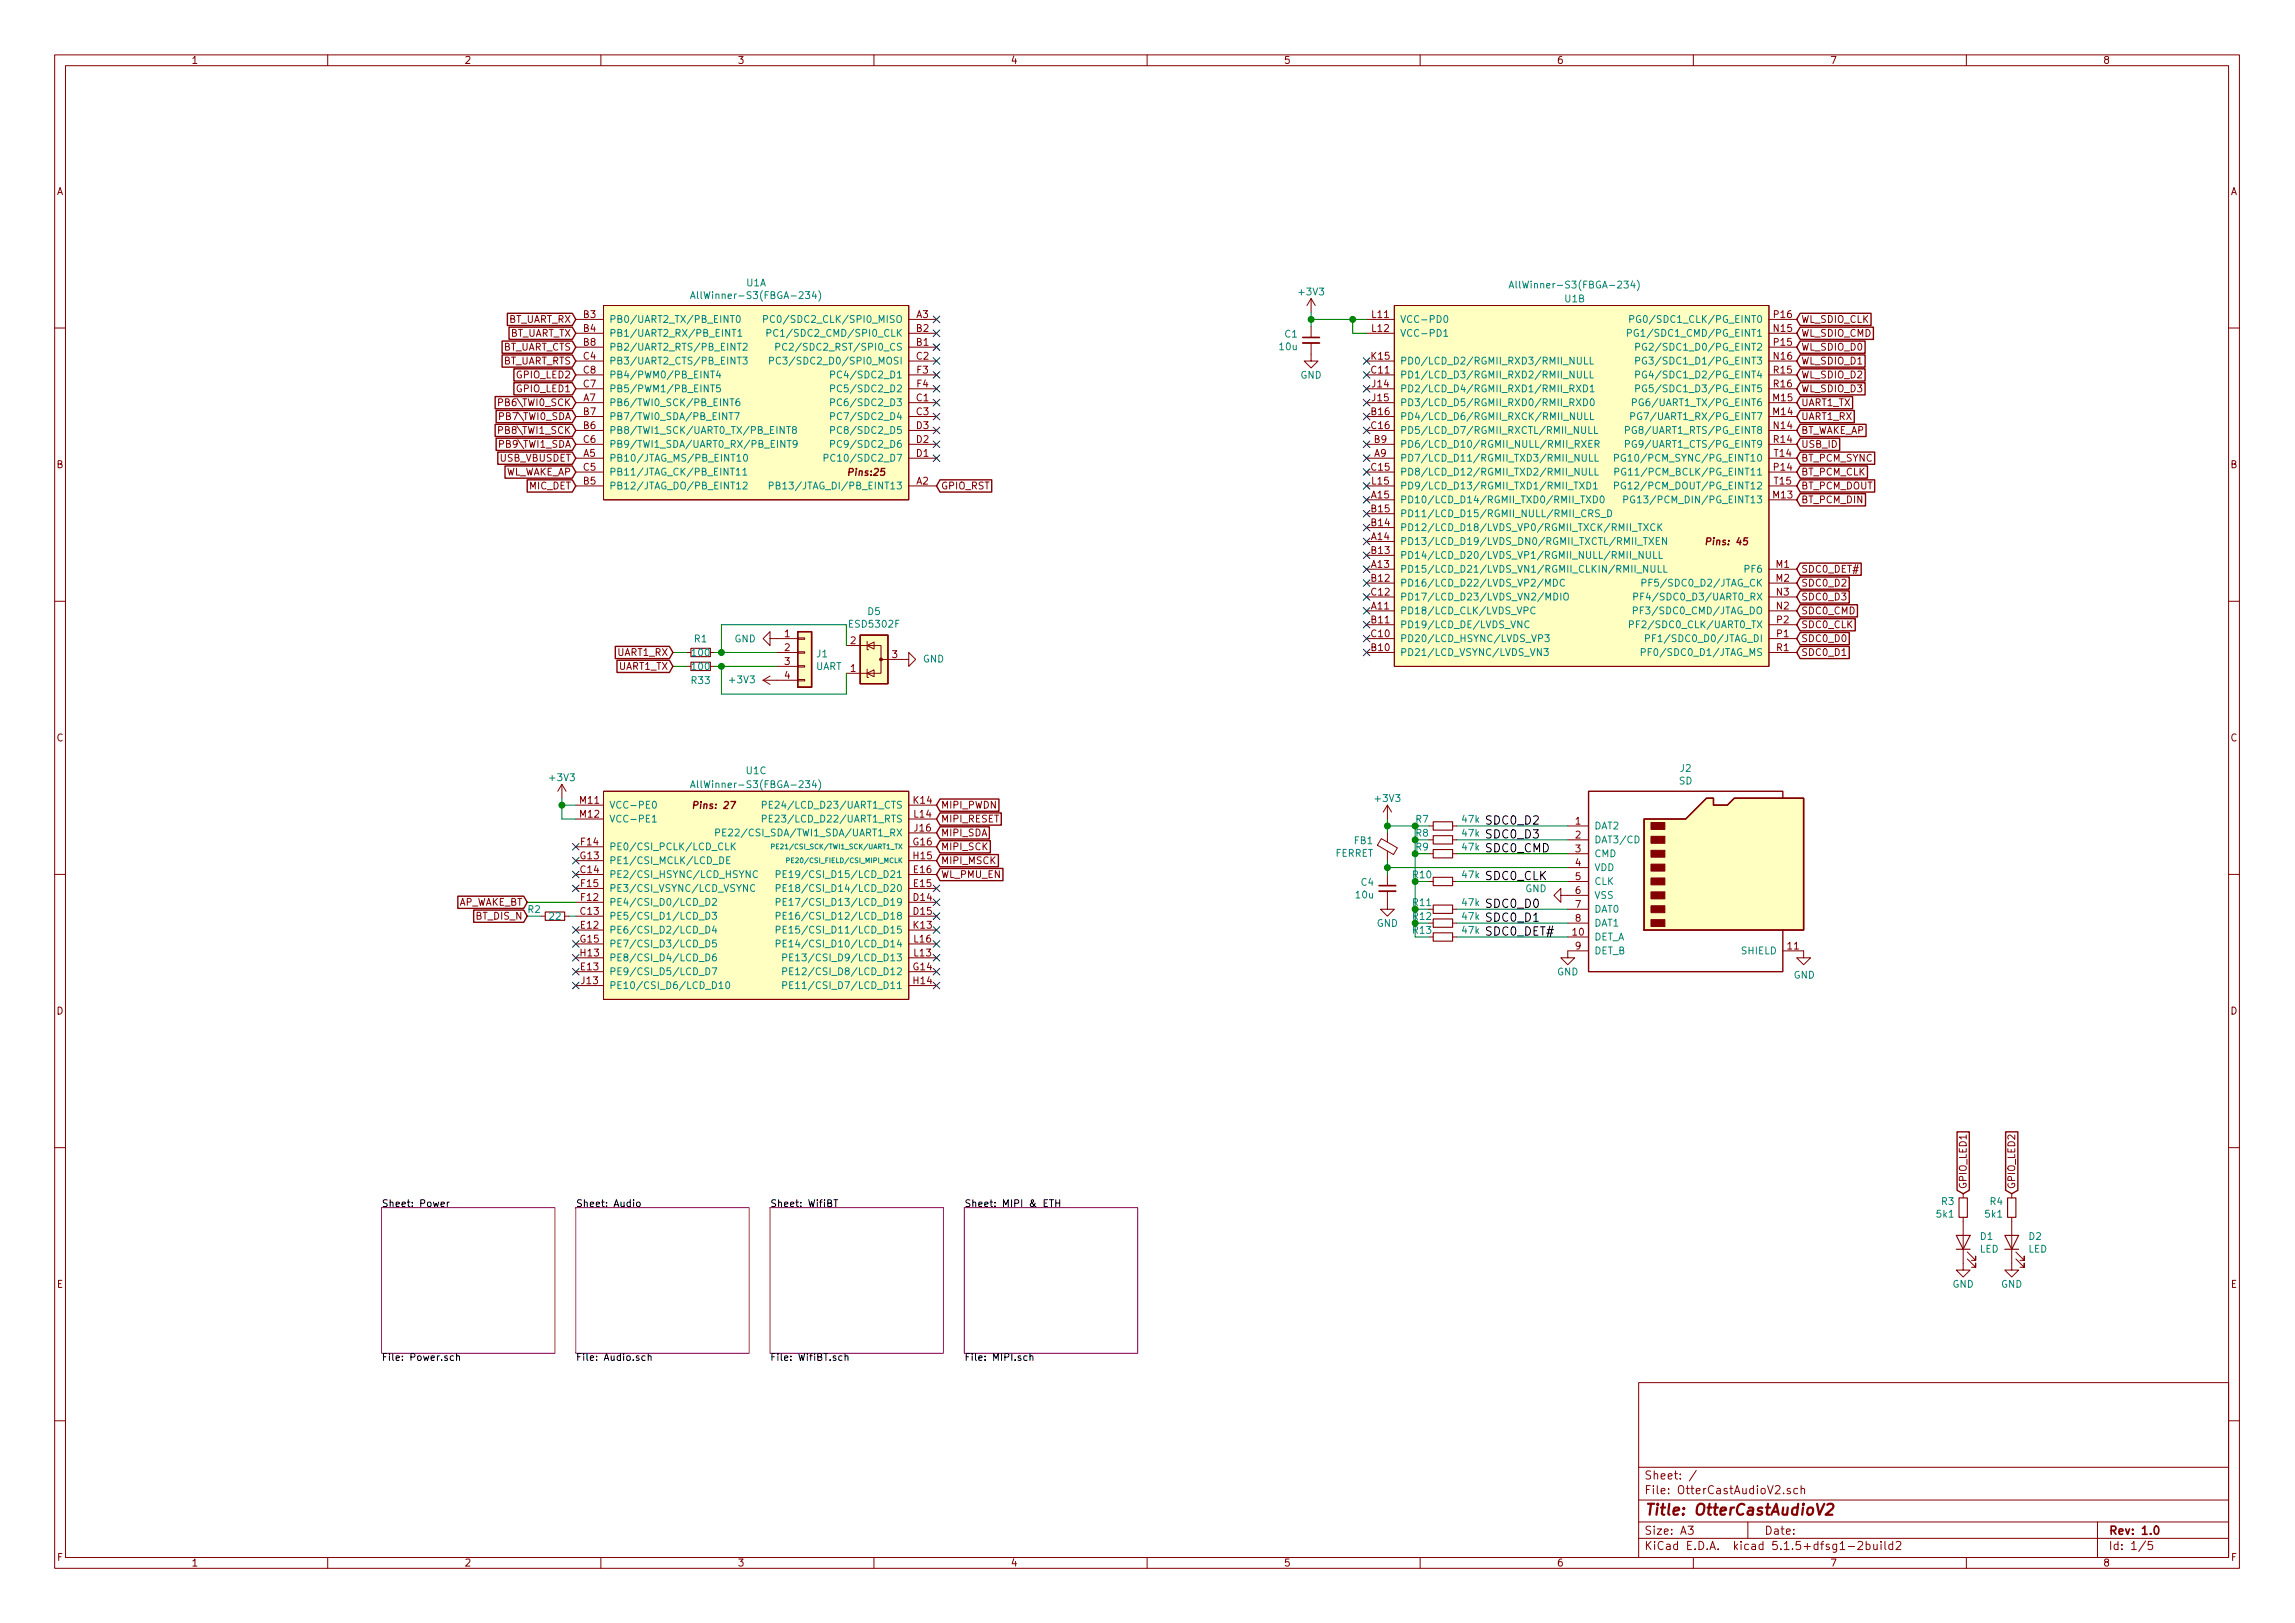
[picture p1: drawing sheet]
<svg xmlns="http://www.w3.org/2000/svg" width="420mm" height="297mm" viewBox="0 0 420 297" stroke-linecap="round" stroke-linejoin="round" font-family="sans-serif">
<defs><g id="words">
<text font-size="2.8" fill="#840000" x="301" y="277.3">Title: OtterCastAudioV2</text>
<g font-size="2.1">
<text x="271.8" y="153.5">SDC0_D3</text>
<text x="271.8" y="150.9">SDC0_D2</text>
<text x="271.8" y="156">SDC0_CMD</text>
<text x="271.8" y="161.1">SDC0_CLK</text>
<text x="271.8" y="166.2">SDC0_D0</text>
<text x="271.8" y="171.2">SDC0_DET#</text>
<text x="271.8" y="168.7">SDC0_D1</text>
</g>
<g font-size="2.1" fill="#840000">
<text x="301" y="273.5">File: OtterCastAudioV2.sch</text>
<text x="301" y="270.8">Sheet: /</text>
<text x="301" y="280.9">Size: A3</text>
<text x="323" y="280.9">Date:</text>
<text x="386" y="280.9">Rev: 1.0</text>
<text x="301" y="283.7">KiCad E.D.A. kicad 5.1.5+dfsg1-2build2</text>
<text x="386" y="283.7">Id: 1/5</text>
</g>
<g font-size="1.8" fill="#840000">
<text x="35" y="11.7">1</text>
<text x="85" y="11.7">2</text>
<text x="135" y="11.7">3</text>
<text x="185" y="11.7">4</text>
<text x="235" y="11.7">5</text>
<text x="285" y="11.7">6</text>
<text x="335" y="11.7">7</text>
<text x="385" y="11.7">8</text>
<text x="10.4" y="35.7">A</text>
<text x="408.4" y="35.7">A</text>
<text x="92.9" y="59.1">BT_UART_RX</text>
<text x="106.8" y="58.2">B3</text>
<text x="167.8" y="58.2">A3</text>
<text x="251.2" y="58.2">L11</text>
<text x="324.8" y="58.2">P16</text>
<text x="329.7" y="59.1">WL_SDIO_CLK</text>
<text x="91.8" y="64.2">BT_UART_CTS</text>
<text x="93.1" y="61.6">BT_UART_TX</text>
<text x="106.8" y="60.7">B4</text>
<text x="106.8" y="63.3">B8</text>
<text x="106.8" y="65.8">C4</text>
<text x="167.8" y="63.3">B1</text>
<text x="167.8" y="60.7">B2</text>
<text x="167.8" y="65.8">C2</text>
<text x="251.1" y="65.8">K15</text>
<text x="251.2" y="60.7">L12</text>
<text x="324.8" y="60.7">N15</text>
<text x="324.8" y="65.8">N16</text>
<text x="324.8" y="63.3">P15</text>
<text x="329.7" y="61.6">WL_SDIO_CMD</text>
<text x="329.7" y="64.2">WL_SDIO_D0</text>
<text x="91.8" y="66.7">BT_UART_RTS</text>
<text x="94.7" y="71.8">GPIO_LED1</text>
<text x="94.7" y="69.3">GPIO_LED2</text>
<text x="106.8" y="70.9">C7</text>
<text x="106.8" y="68.4">C8</text>
<text x="167.9" y="68.4">F3</text>
<text x="167.9" y="70.9">F4</text>
<text x="251.1" y="68.4">C11</text>
<text x="251.3" y="70.9">J14</text>
<text x="324.8" y="68.4">R15</text>
<text x="324.8" y="70.9">R16</text>
<text x="329.7" y="69.3">WL_SDIO_D2</text>
<text x="329.7" y="66.7">WL_SDIO_D1</text>
<text x="329.7" y="71.8">WL_SDIO_D3</text>
<text x="91.7" y="74.3">PB6\TWI0_SCK</text>
<text x="91.7" y="76.9">PB7\TWI0_SDA</text>
<text x="106.8" y="73.4">A7</text>
<text x="106.8" y="76">B7</text>
<text x="167.8" y="73.4">C1</text>
<text x="167.8" y="76">C3</text>
<text x="251.1" y="76">B16</text>
<text x="251.3" y="73.4">J15</text>
<text x="324.7" y="76">M14</text>
<text x="324.7" y="73.4">M15</text>
<text x="329.7" y="74.3">UART1_TX</text>
<text x="329.7" y="76.9">UART1_RX</text>
<text x="91.7" y="79.4">PB8\TWI1_SCK</text>
<text x="91.7" y="82">PB9\TWI1_SDA</text>
<text x="106.8" y="83.6">A5</text>
<text x="106.8" y="78.5">B6</text>
<text x="106.8" y="81.1">C6</text>
<text x="167.8" y="83.6">D1</text>
<text x="167.8" y="81.1">D2</text>
<text x="167.8" y="78.5">D3</text>
<text x="251.1" y="78.5">C16</text>
<text x="251.6" y="83.6">A9</text>
<text x="251.6" y="81.1">B9</text>
<text x="324.8" y="78.5">N14</text>
<text x="324.8" y="81.1">R14</text>
<text x="324.9" y="83.6">T14</text>
<text x="329.7" y="82">USB_ID</text>
<text x="329.7" y="79.4">BT_WAKE_AP</text>
<text x="10.4" y="85.7">B</text>
<text x="91.5" y="84.5">USB_VBUSDET</text>
<text x="92" y="87">WL_WAKE_AP</text>
<text x="96.9" y="89.6">MIC_DET</text>
<text x="106.8" y="88.7">B5</text>
<text x="106.8" y="86.1">C5</text>
<text x="155.6" y="87.1">Pins:25</text>
<text x="167.8" y="88.7">A2</text>
<text x="172.2" y="89.6">GPIO_RST</text>
<text x="251.1" y="86.1">C15</text>
<text x="251.2" y="88.7">L15</text>
<text x="324.8" y="86.1">P14</text>
<text x="324.9" y="88.7">T15</text>
<text x="329.7" y="84.5">BT_PCM_SYNC</text>
<text x="329.7" y="87">BT_PCM_CLK</text>
<text x="329.7" y="89.6">BT_PCM_DOUT</text>
<text x="408.4" y="85.7">B</text>
<text x="251.1" y="91.2">A15</text>
<text x="251.1" y="93.8">B15</text>
<text x="324.7" y="91.2">M13</text>
<text x="329.7" y="92.1">BT_PCM_DIN</text>
<text x="251.1" y="98.8">A14</text>
<text x="251.1" y="101.4">B13</text>
<text x="251.1" y="96.3">B14</text>
<text x="312.9" y="99.8">Pins: 45</text>
<text x="251.1" y="103.9">A13</text>
<text x="251.1" y="106.5">B12</text>
<text x="325.2" y="103.9">M1</text>
<text x="325.2" y="106.5">M2</text>
<text x="329.7" y="104.8">SDC0_DET#</text>
<text x="329.7" y="107.4">SDC0_D2</text>
<text x="251.1" y="111.5">A11</text>
<text x="251.1" y="109">C12</text>
<text x="325.3" y="111.5">N2</text>
<text x="325.3" y="109">N3</text>
<text x="329.7" y="109.9">SDC0_D3</text>
<text x="329.7" y="112.4">SDC0_CMD</text>
<text x="143.7" y="116.6">1</text>
<text x="143.7" y="119.2">2</text>
<text x="155.7" y="117.9">2</text>
<text x="251.1" y="119.2">B10</text>
<text x="251.1" y="114.1">B11</text>
<text x="251.1" y="116.6">C10</text>
<text x="325.3" y="119.2">R1</text>
<text x="325.3" y="116.6">P1</text>
<text x="325.3" y="114.1">P2</text>
<text x="329.7" y="117.5">SDC0_D0</text>
<text x="329.7" y="115">SDC0_CLK</text>
<text x="113.1" y="120.1">UART1_RX</text>
<text x="113.3" y="122.6">UART1_TX</text>
<text x="143.7" y="121.7">3</text>
<text x="143.7" y="124.2">4</text>
<text x="155.7" y="123">1</text>
<text x="163.3" y="120.4">3</text>
<text x="329.7" y="120.1">SDC0_D1</text>
<text x="10.4" y="135.7">C</text>
<text x="408.4" y="135.7">C</text>
<text x="106.2" y="147.1">M11</text>
<text x="106.2" y="149.6">M12</text>
<text x="127.4" y="148">Pins: 27</text>
<text x="167.3" y="147.1">K14</text>
<text x="167.4" y="149.6">L14</text>
<text x="172.2" y="148">MIPI_PWDN</text>
<text x="106.4" y="154.7">F14</text>
<text x="167.2" y="154.7">G16</text>
<text x="167.4" y="152.2">J16</text>
<text x="172.2" y="153.1">MIPI_SDA</text>
<text x="172.2" y="155.6">MIPI_SCK</text>
<text x="172.2" y="150.5">MIPI_RESET</text>
<text x="288.4" y="150.9">1</text>
<text x="288.4" y="153.5">2</text>
<text x="288.4" y="156">3</text>
<text x="106.3" y="157.3">G13</text>
<text x="106.3" y="159.8">C14</text>
<text x="167.3" y="157.3">H15</text>
<text x="167.3" y="159.8">E16</text>
<text x="172.2" y="158.2">MIPI_MSCK</text>
<text x="172.2" y="160.7">WL_PMU_EN</text>
<text x="288.4" y="158.5">4</text>
<text x="288.4" y="161.1">5</text>
<text x="83.5" y="165.8">AP_WAKE_BT</text>
<text x="106.3" y="167.4">C13</text>
<text x="106.4" y="164.9">F12</text>
<text x="106.4" y="162.3">F15</text>
<text x="167.3" y="164.9">D14</text>
<text x="167.3" y="167.4">D15</text>
<text x="167.3" y="162.3">E15</text>
<text x="288.4" y="163.6">6</text>
<text x="288.4" y="166.2">7</text>
<text x="87.2" y="168.3">BT_DIS_N</text>
<text x="106.3" y="172.5">G15</text>
<text x="106.4" y="170">E12</text>
<text x="167.3" y="170">K13</text>
<text x="167.4" y="172.5">L16</text>
<text x="288" y="171.2">10</text>
<text x="288.4" y="168.7">8</text>
<text x="288.4" y="173.8">9</text>
<text x="327.3" y="173.8">11</text>
<text x="106.3" y="175">H13</text>
<text x="106.4" y="177.6">E13</text>
<text x="167.2" y="177.6">G14</text>
<text x="167.4" y="175">L13</text>
<text x="10.4" y="185.7">D</text>
<text x="106.5" y="180.1">J13</text>
<text x="167.3" y="180.1">H14</text>
<text x="408.4" y="185.7">D</text>
<text x="360" y="217.7" transform="rotate(-90 360 217.7)">GPIO_LED1</text>
<text x="368.9" y="217.7" transform="rotate(-90 368.9 217.7)">GPIO_LED2</text>
<text x="10.4" y="235.7">E</text>
<text x="408.4" y="235.7">E</text>
<text x="10.5" y="285.7">F</text>
<text x="35" y="286.7">1</text>
<text x="85" y="286.7">2</text>
<text x="135" y="286.7">3</text>
<text x="185" y="286.7">4</text>
<text x="235" y="286.7">5</text>
<text x="285" y="286.7">6</text>
<text x="335" y="286.7">7</text>
<text x="385" y="286.7">8</text>
<text x="408.5" y="285.7">F</text>
</g>
<g font-size="1.8" fill="#008484">
<text x="136.7" y="52.4">U1A</text>
<text x="277.9" y="52.8">AllWinner-S3(FBGA-234)</text>
<text x="111.5" y="59.1">PB0/UART2_TX/PB_EINT0</text>
<text x="128.1" y="54.7">AllWinner-S3(FBGA-234)</text>
<text x="142.3" y="59.1">PC0/SDC2_CLK/SPI0_MISO</text>
<text x="237.9" y="54.1">+3V3</text>
<text x="256.3" y="59.1">VCC-PD0</text>
<text x="286.5" y="55.3">U1B</text>
<text x="300.4" y="59.1">PG0/SDC1_CLK/PG_EINT0</text>
<text x="111.5" y="61.6">PB1/UART2_RX/PB_EINT1</text>
<text x="111.5" y="64.2">PB2/UART2_RTS/PB_EINT2</text>
<text x="142.7" y="61.6">PC1/SDC2_CMD/SPI0_CLK</text>
<text x="144.4" y="64.2">PC2/SDC2_RST/SPI0_CS</text>
<text x="234.3" y="64.1">10u</text>
<text x="235.3" y="61.8">C1</text>
<text x="256.3" y="61.6">VCC-PD1</text>
<text x="300" y="61.6">PG1/SDC1_CMD/PG_EINT1</text>
<text x="301.8" y="64.2">PG2/SDC1_D0/PG_EINT2</text>
<text x="111.5" y="66.7">PB3/UART2_CTS/PB_EINT3</text>
<text x="111.5" y="71.8">PB5/PWM1/PB_EINT5</text>
<text x="111.5" y="69.3">PB4/PWM0/PB_EINT4</text>
<text x="143.6" y="66.7">PC3/SDC2_D0/SPI0_MOSI</text>
<text x="153.5" y="69.3">PC4/SDC2_D1</text>
<text x="153.5" y="71.8">PC5/SDC2_D2</text>
<text x="238.1" y="69.3">GND</text>
<text x="256.3" y="69.3">PD1/LCD_D3/RGMII_RXD2/RMII_NULL</text>
<text x="256.3" y="71.8">PD2/LCD_D4/RGMII_RXD1/RMII_RXD1</text>
<text x="256.3" y="66.7">PD0/LCD_D2/RGMII_RXD3/RMII_NULL</text>
<text x="301.8" y="66.7">PG3/SDC1_D1/PG_EINT3</text>
<text x="301.8" y="69.3">PG4/SDC1_D2/PG_EINT4</text>
<text x="301.8" y="71.8">PG5/SDC1_D3/PG_EINT5</text>
<text x="111.5" y="74.3">PB6/TWI0_SCK/PB_EINT6</text>
<text x="111.5" y="76.9">PB7/TWI0_SDA/PB_EINT7</text>
<text x="153.5" y="74.3">PC6/SDC2_D3</text>
<text x="153.5" y="76.9">PC7/SDC2_D4</text>
<text x="256.3" y="76.9">PD4/LCD_D6/RGMII_RXCK/RMII_NULL</text>
<text x="256.3" y="74.3">PD3/LCD_D5/RGMII_RXD0/RMII_RXD0</text>
<text x="300.4" y="76.9">PG7/UART1_RX/PG_EINT7</text>
<text x="300.6" y="74.3">PG6/UART1_TX/PG_EINT6</text>
<text x="111.5" y="79.4">PB8/TWI1_SCK/UART0_TX/PB_EINT8</text>
<text x="111.5" y="82">PB9/TWI1_SDA/UART0_RX/PB_EINT9</text>
<text x="153.5" y="82">PC9/SDC2_D6</text>
<text x="153.5" y="79.4">PC8/SDC2_D5</text>
<text x="256.3" y="82">PD6/LCD_D10/RGMII_NULL/RMII_RXER</text>
<text x="256.3" y="79.4">PD5/LCD_D7/RGMII_RXCTL/RMII_NULL</text>
<text x="299.3" y="79.4">PG8/UART1_RTS/PG_EINT8</text>
<text x="299.3" y="82">PG9/UART1_CTS/PG_EINT9</text>
<text x="111.5" y="84.5">PB10/JTAG_MS/PB_EINT10</text>
<text x="111.5" y="89.6">PB12/JTAG_DO/PB_EINT12</text>
<text x="111.5" y="87">PB11/JTAG_CK/PB_EINT11</text>
<text x="143.1" y="89.6">PB13/JTAG_DI/PB_EINT13</text>
<text x="152.5" y="84.5">PC10/SDC2_D7</text>
<text x="256.3" y="84.5">PD7/LCD_D11/RGMII_TXD3/RMII_NULL</text>
<text x="256.3" y="87">PD8/LCD_D12/RGMII_TXD2/RMII_NULL</text>
<text x="256.3" y="89.6">PD9/LCD_D13/RGMII_TXD1/RMII_TXD1</text>
<text x="297.9" y="89.6">PG12/PCM_DOUT/PG_EINT12</text>
<text x="298" y="87">PG11/PCM_BCLK/PG_EINT11</text>
<text x="298" y="84.5">PG10/PCM_SYNC/PG_EINT10</text>
<text x="256.3" y="92.1">PD10/LCD_D14/RGMII_TXD0/RMII_TXD0</text>
<text x="256.3" y="94.7">PD11/LCD_D15/RGMII_NULL/RMII_CRS_D</text>
<text x="299.8" y="92.1">PG13/PCM_DIN/PG_EINT13</text>
<text x="256.3" y="99.7">PD13/LCD_D19/LVDS_DN0/RGMII_TXCTL/RMII_TXEN</text>
<text x="256.3" y="97.2">PD12/LCD_D18/LVDS_VP0/RGMII_TXCK/RMII_TXCK</text>
<text x="256.3" y="104.8">PD15/LCD_D21/LVDS_VN1/RGMII_CLKIN/RMII_NULL</text>
<text x="256.3" y="107.4">PD16/LCD_D22/LVDS_VP2/MDC</text>
<text x="256.3" y="102.3">PD14/LCD_D20/LVDS_VP1/RGMII_NULL/RMII_NULL</text>
<text x="302.4" y="107.4">PF5/SDC0_D2/JTAG_CK</text>
<text x="319.6" y="104.8">PF6</text>
<text x="158.9" y="112.6">D5</text>
<text x="256.3" y="112.4">PD18/LCD_CLK/LVDS_VPC</text>
<text x="256.3" y="109.9">PD17/LCD_D23/LVDS_VN2/MDIO</text>
<text x="300.5" y="112.4">PF3/SDC0_CMD/JTAG_DO</text>
<text x="301.3" y="109.9">PF4/SDC0_D3/UART0_RX</text>
<text x="127.2" y="117.6">R1</text>
<text x="134.5" y="117.6">GND</text>
<text x="155.7" y="114.9">ESD5302F</text>
<text x="256.3" y="115">PD19/LCD_DE/LVDS_VNC</text>
<text x="256.3" y="117.5">PD20/LCD_HSYNC/LVDS_VP3</text>
<text x="300.1" y="115">PF2/SDC0_CLK/UART0_TX</text>
<text x="303.2" y="117.5">PF1/SDC0_D0/JTAG_DI</text>
<text x="126.6" y="125.2">R33</text>
<text x="126.8" y="122.6">100</text>
<text x="126.8" y="120.1">100</text>
<text x="133.7" y="125.1">+3V3</text>
<text x="149.3" y="122.6">UART</text>
<text x="149.6" y="120.3">J1</text>
<text x="169" y="121.2">GND</text>
<text x="256.3" y="120.1">PD21/LCD_VSYNC/LVDS_VN3</text>
<text x="302.3" y="120.1">PF0/SDC0_D1/JTAG_MS</text>
<text x="100.8" y="143">+3V3</text>
<text x="136.7" y="141.7">U1C</text>
<text x="307.4" y="143.6">SD</text>
<text x="307.6" y="141.3">J2</text>
<text x="111.5" y="148">VCC-PE0</text>
<text x="128.1" y="144.2">AllWinner-S3(FBGA-234)</text>
<text x="141.8" y="148">PE24/LCD_D23/UART1_CTS</text>
<text x="251.9" y="146.8">+3V3</text>
<text x="111.5" y="155.6">PE0/CSI_PCLK/LCD_CLK</text>
<text x="111.5" y="150.5">VCC-PE1</text>
<text x="133.6" y="153.1">PE22/CSI_SDA/TWI1_SDA/UART1_RX</text>
<text x="141.8" y="150.5">PE23/LCD_D22/UART1_RTS</text>
<text x="248" y="154.5">FB1</text>
<text x="267.8" y="153.1">47k</text>
<text x="267.8" y="155.7">47k</text>
<text x="267.8" y="150.6">47k</text>
<text x="291.8" y="151.8">DAT2</text>
<text x="291.8" y="154.3">DAT3/CD</text>
<text x="111.5" y="160.7">PE2/CSI_HSYNC/LCD_HSYNC</text>
<text x="111.5" y="158.2">PE1/CSI_MCLK/LCD_DE</text>
<text x="145" y="160.7">PE19/CSI_D15/LCD_D21</text>
<text x="244.4" y="156.8">FERRET</text>
<text x="267.8" y="160.7">47k</text>
<text x="291.8" y="156.9">CMD</text>
<text x="291.8" y="159.4">VDD</text>
<text x="291.8" y="162">CLK</text>
<text x="111.5" y="165.8">PE4/CSI_D0/LCD_D2</text>
<text x="111.5" y="163.2">PE3/CSI_VSYNC/LCD_VSYNC</text>
<text x="145" y="165.8">PE17/CSI_D13/LCD_D19</text>
<text x="145" y="163.2">PE18/CSI_D14/LCD_D20</text>
<text x="248.3" y="164.4">10u</text>
<text x="249.2" y="162.1">C4</text>
<text x="267.8" y="165.8">47k</text>
<text x="279.2" y="163.3">GND</text>
<text x="291.8" y="164.5">VSS</text>
<text x="291.8" y="167">DAT0</text>
<text x="100.6" y="168.4">22</text>
<text x="111.5" y="168.3">PE5/CSI_D1/LCD_D3</text>
<text x="111.5" y="170.9">PE6/CSI_D2/LCD_D4</text>
<text x="111.5" y="173.4">PE7/CSI_D3/LCD_D5</text>
<text x="145" y="168.3">PE16/CSI_D12/LCD_D18</text>
<text x="145" y="170.9">PE15/CSI_D11/LCD_D15</text>
<text x="145" y="173.4">PE14/CSI_D10/LCD_D14</text>
<text x="252" y="169.6">GND</text>
<text x="267.8" y="170.9">47k</text>
<text x="267.8" y="168.4">47k</text>
<text x="291.8" y="172.1">DET_A</text>
<text x="291.8" y="169.6">DAT1</text>
<text x="111.5" y="178.5">PE9/CSI_D5/LCD_D7</text>
<text x="111.5" y="175.9">PE8/CSI_D4/LCD_D6</text>
<text x="146" y="178.5">PE12/CSI_D8/LCD_D12</text>
<text x="146" y="175.9">PE13/CSI_D9/LCD_D13</text>
<text x="285.1" y="178.5">GND</text>
<text x="291.8" y="174.7">DET_B</text>
<text x="318.9" y="174.7">SHIELD</text>
<text x="328.4" y="179.1">GND</text>
<text x="111.5" y="181">PE10/CSI_D6/LCD_D10</text>
<text x="146" y="181">PE11/CSI_D7/LCD_D11</text>
<text x="355.5" y="220.5">R3</text>
<text x="364.4" y="220.5">R4</text>
<text x="354.6" y="222.8">5k1</text>
<text x="362.6" y="226.9">D1</text>
<text x="363.5" y="222.8">5k1</text>
<text x="371.5" y="226.9">D2</text>
<text x="362.4" y="229.2">LED</text>
<text x="371.3" y="229.2">LED</text>
<text x="357.5" y="235.7">GND</text>
<text x="366.3" y="235.7">GND</text>
</g>
<g font-size="1.8" fill="#008400">
<text x="259.2" y="153.1">R8</text>
<text x="259.2" y="155.7">R9</text>
<text x="259.2" y="150.6">R7</text>
<text x="258.7" y="160.7">R10</text>
<text x="96.7" y="167.1">R2</text>
<text x="258.7" y="165.8">R11</text>
<text x="258.7" y="170.9">R13</text>
<text x="258.7" y="168.4">R12</text>
</g>
<g font-size="1.8">
<text x="69.8" y="220.9">Sheet: Power</text>
<text x="105.4" y="220.9">Sheet: Audio</text>
<text x="141" y="220.9">Sheet: WifiBT</text>
<text x="176.5" y="220.9">Sheet: MIPI &amp; ETH</text>
<text x="69.8" y="249.1">File: Power.sch</text>
<text x="105.4" y="249.1">File: Audio.sch</text>
<text x="141" y="249.1">File: WifiBT.sch</text>
<text x="176.5" y="249.1">File: MIPI.sch</text>
</g>
<g font-size="1.2" fill="#008484">
<text x="143.3" y="155.4">PE21/CSI_SCK/TWI1_SCK/UART1_TX</text>
<text x="145.7" y="157.9">PE20/CSI_FIELD/CSI_MIPI_MCLK</text>
</g>
</g></defs>
<g fill="none" stroke="#840000" stroke-width=".18">
<path d="M10 10h400v277h-400zM12 12h396v273.1h-396zM60 10v2M110 10v2M160 10v2M210 10v2M260 10v2M310 10v2M360 10v2M105.4 58.5h5.1M110.5 55.9h55.9v35.6h-55.9zM166.4 58.5h5"/>
<path d="M240 54.6v2.6M240 59.7v2.1M240 54.6l-.7 1.3M240 54.6l.8 1.3M250.2 58.5h5.1M255.3 55.9h68.5v66.1h-68.5zM323.8 58.5h5.1M10 60h2M105.4 73.7h5.1M105.4 63.5h5.1M105.4 61h5.1M105.4 78.8h5.1"/>
<path d="M105.4 76.2h5.1M105.4 66.1h5.1M105.4 71.2h5.1M105.4 68.6h5.1M166.4 73.7h5M166.4 63.5h5M166.4 61h5M166.4 78.8h5M166.4 76.2h5M166.4 66.1h5M166.4 71.2h5M166.4 68.6h5"/>
<path d="M240 62.8v3.3h1.3l-1.3 1.2-1.2-1.2h1.2M250.2 73.7h5.1M250.2 61h5.1M250.2 78.8h5.1M250.2 76.2h5.1M250.2 66.1h5.1M250.2 71.2h5.1M250.2 68.6h5.1M323.8 73.7h5.1M323.8 63.5h5.1M323.8 61h5.1M323.8 78.8h5.1"/>
<path d="M323.8 76.2h5.1M323.8 66.1h5.1M323.8 71.2h5.1M323.8 68.6h5.1M408 60h2M105.4 88.9h5.1M105.4 83.9h5.1M105.4 86.4h5.1M105.4 81.3h5.1M166.4 88.9h5M166.4 83.9h5M166.4 81.3h5"/>
<path d="M250.2 88.9h5.1M250.2 83.9h5.1M250.2 86.4h5.1M250.2 81.3h5.1M250.2 99.1h5.1M250.2 91.5h5.1M250.2 96.6h5.1M250.2 94h5.1M323.8 88.9h5.1M323.8 83.9h5.1M323.8 86.4h5.1M323.8 81.3h5.1"/>
<path d="M323.8 91.5h5.1M10 110h2M125.7 119.4h.8M130 119.4h.8M141 116.9v-1.3l-1.3 1.3 1.3 1.2v-1.2h5M142.2 119.4h3.8M146 116.7h1.3v.3h-1.3zM146 119.3h1.3v.2h-1.3zM154.9 118.1h3.8M158.7 118.1h2.6v5.1h-2.6M158.7 117.4v1.5h.3M158.7 118.1l1.3-.6v1.3z"/>
<path d="M250.2 111.8h5.1M250.2 104.2h5.1M250.2 119.4h5.1M250.2 114.3h5.1M250.2 106.7h5.1M250.2 101.6h5.1M250.2 116.9h5.1M250.2 109.3h5.1M323.8 111.8h5.1M323.8 104.2h5.1M323.8 119.4h5.1M323.8 114.3h5.1"/>
<path d="M323.8 106.7h5.1M323.8 116.9h5.1M323.8 109.3h5.1M408 110h2M125.7 122h.8M130 122h.8M139.7 124.5l1.3 .8M139.7 124.5h6.3M141 123.7l-1.3 .8M142.2 122h3.8M146 124.4h1.3v.2h-1.3zM146 121.8h1.3v.3h-1.3z"/>
<path d="M154.9 123.2h3.8M158.7 122.5v1.5h.3M158.7 123.2l1.3-.6v1.3zM161.3 120.7h5.1v-1.3l1.2 1.3-1.2 1.3v-1.3M301 122h.1M102.9 143.5l-.8 1.3M102.9 143.5v2.6M102.9 143.5l.7 1.3M105.4 155h5.1M105.4 157.5h5.1M105.4 147.4h5.1M105.4 149.9h5.1"/>
<path d="M110.5 144.8h55.9v38.1h-55.9zM166.4 155h5M166.4 157.5h5M166.4 152.4h5M166.4 147.4h5M166.4 149.9h5M252.9 153.5l2.9 1.7-.7 1.2-2.9-1.7zM254 147.4v2.5M254 152.4v1.7M254 155.8v1.7M254 147.4l-.8 1.2M254 147.4l.8 1.2"/>
<path d="M261.6 153.7h.8M261.6 156.2h.8M261.6 151.2h.8M265.9 153.7h.8M265.9 156.2h.8M265.9 151.2h.8M287 153.7h3.8M287 156.2h3.8M287 151.2h3.8M287 158.8h3.8M10 160h2M99.1 167.7h.7"/>
<path d="M103.4 167.7h.7M105.4 160.1h5.1M105.4 167.7h5.1M105.4 165.1h5.1M105.4 170.2h5.1M105.4 177.8h5.1M105.4 162.6h5.1M105.4 172.8h5.1M105.4 175.3h5.1M166.4 160.1h5M166.4 167.7h5M166.4 165.1h5"/>
<path d="M166.4 170.2h5M166.4 177.8h5M166.4 162.6h5M166.4 172.8h5M166.4 175.3h5M254 163.1v3.3h1.3l-1.3 1.3-1.3-1.3h1.3M254 160.1v2M261.6 166.4h.8M265.9 171.5h.8M265.9 168.9h.8M265.9 161.3h.8M265.9 166.4h.8"/>
<path d="M285.7 163.9v-1.3l-1.2 1.3 1.2 1.2v-1.2h5.1M287 171.5h3.8M287 168.9h3.8M287 161.3h3.8M287 166.4h3.8M290.8 174h-3.8v1.3h1.3l-1.3 1.3-1.3-1.3h1.3M326.4 174h3.8v1.3h1.3l-1.3 1.3-1.3-1.3h1.3M408 160h2M105.4 180.4h5.1M166.4 180.4h5M10 210h2M359.4 218.5v.7"/>
<path d="M368.3 218.5v.7M408 210h2M359.4 222.8v9.6h-1.3l1.3 1.3 1.3-1.3h-1.3M360.2 230.4l1.5 1.5v-.7v.7h-.8M360.2 229.1l1.5 1.6v-.8v.8h-.8M368.3 222.8v9.6h-1.3l1.3 1.3 1.3-1.3h-1.3M369.1 230.4l1.5 1.5v-.7v.7h-.8M369.1 229.1l1.5 1.6v-.8v.8h-.8M300 253h108v32.1h-108zM10 260h2M300 278.5h108M300 274.5h108"/>
<path d="M300 268.5h108M309 279.3h1l-.5 .6 .4 .1v.7l-.2 .1-.7-.1M310.5 269.1l-1.2 2M320 278.5v3M327.7 272.5l-.3-.1-.2 .2 .1 .2 .4 .2v.3h-.5M329.1 272.5l-.4-.1-.3 .3v.6l.3 .1 .4-.1M329.7 272.5l.2-.1 .4 .1 .1 .9M329.7 271.9v1.5M384 278.5v6.6M408 260h2M60 285.1v1.9M110 285.1v1.9"/>
<path d="M160 285.1v1.9M210 285.1v1.9M260 285.1v1.9M300 281.5h108M310 285.1v1.9M338.4 283h1.1M340.2 282.3l.5-.2 .3 .4-.9 1.1h.9M341.7 282.7l.4-.1 .3 .3-.2 .6h-.5M341.7 282.1v1.5M343 282.6l.1 .9 .3 .1 .3-.1M343.7 282.6v1M344.4 282.1v.2"/>
<path d="M344.4 282.6v1M345.1 282.1v1.3l.2 .2M346.5 282.7l-.4-.1-.3 .3 .1 .6 .2 .1 .4-.1M346.5 282.1v1.5M347.1 282.3l.6-.2 .3 .4-.9 1.1h.9M360 285.1v1.9M392.8 282l-1.3 2M394 282.1h-.7l-.1 .7 .3-.1h.5l.1 .3-.1 .5-.2 .1-.6-.1"/>
</g>
<path d="M238.5 61.8h3.1M252.5 162.1h3M394.5 279.5l.2-.2a.81 .81 0 0 1 .6 .6 .81 .81 0 0 1-.3 .8l-.1 .1a.79 .79 0 0 1-.4-1.3z" fill="none" stroke="#840000" stroke-width=".3"/>
<path d="M332.7 275.2l.4 2 .9-2M334.5 275.4l.3-.2h.5l.3 .2v.4l-.1 .3-1.3 1.1h1.3" fill="none" stroke="#840000" stroke-width=".41"/>
<path d="M69.8 221h31.8v26.7h-31.8zM105.4 221h31.8v26.7h-31.8zM141 221h31.7v26.7h-31.7zM176.5 221h31.8v26.7h-31.8z" fill="none" stroke="#840084" stroke-width=".18"/>
<g fill="none" stroke="#000" stroke-width=".18">
<path d="M152.7 219.6h.7M153 219.6v1.2M192.1 219.6h.8M192.5 219.6v1.2M193.3 219.6v1.2M194 219.6v1.2M80.7 220.4l.7-.1-.1-.2-.4-.1-.2 .2 .1 .6h.5M81.9 220v.8M82.2 220l-.3 .2M116.7 220.1l.3-.1 .1 .1v.7h-.3l-.3-.2zM193.3 220.2h.7M83 248.2l-.3-.1-.3 .3 .1 .5h.5"/>
<path d="M83.6 248.3l.2-.2 .3 .1v.8M83.6 247.7v1.3M118.1 248.2l-.3-.1-.3 .3 .1 .5h.5M118.7 248.3l.1-.2 .4 .1v.8M118.7 247.7v1.3M154.2 248.2l-.4-.1-.3 .3 .2 .5h.5M154.7 248.3l.2-.2 .3 .1v.8M154.7 247.7v1.3M188 248.2l-.3-.1-.3 .3 .1 .5h.5M188.6 248.3l.1-.2 .4 .1v.8M188.6 247.7v1.3"/>
</g>
<path d="M238.5 62.8h3.1M252.5 163.1h3" fill="none" stroke="#840000" stroke-width=".33"/>
<g fill="none" stroke="#840000" stroke-width=".2">
<path d="M126.5 118.7h3.5v1.5h-3.5zM126.5 121.2h3.5v1.5h-3.5zM262.4 152.9h3.5v1.6h-3.5zM262.4 155.5h3.5v1.5h-3.5zM262.4 150.4h3.5v1.5h-3.5zM99.8 166.9h3.6v1.5h-3.6zM262.4 170.7h3.5v1.5h-3.5zM262.4 168.2h3.5v1.5h-3.5zM262.4 160.6h3.5v1.5h-3.5zM262.4 165.6h3.5v1.6h-3.5zM358.6 219.2h1.6v3.6h-1.6zM367.5 219.2h1.6v3.6h-1.6z"/>
<path d="M358.1 226.1h2.6l-1.3 2.5zM358.1 228.6h2.6M367 226.1h2.6l-1.3 2.5zM367 228.6h2.6"/>
</g>
<g fill="#ffffc2" stroke="#ffffc2" stroke-width=".18">
<path d="M110.5 55.9h55.9v35.6h-55.9z"/>
<path d="M110.5 144.8h55.9v38.1h-55.9z"/>
<path d="M255.3 55.9h68.5v66.1h-68.5z"/>
<path d="M157.5 116.2h5.1v8.9h-5.1z"/>
<path d="M146 115.6h2.6v10.2h-2.6z"/>
<path d="M301 149.9h7.6l3.8-3.8h1.3v1.3h2.5l1.3-1.3h12.7v24.1h-29.2z"/>
</g>
<g fill="none" stroke="#008484" stroke-width=".18">
<path d="M126.4 54.6l.4-1.2 .5 1.2M126.5 54.3h.6M133.7 57.7h.7M134.1 57.7v1.3M134.9 57.9l.2-.2a.69 .69 0 0 1 .4 .7 .69 .69 0 0 1-.4 .6l-.3-.2v-.3zM139.8 58.4h.6l.1-.2v-.3l-.7-.2v1.3M141.8 57.9a.6 .6 0 0 0-.8 .4 .6 .6 0 0 0 .6 .7l.2-.1M149 53.3l-.3 .9h.8M149.3 53.8v.8M149.9 53.2a1.47 1.47 0 0 1 0 1.9M264.5 57.9l.1-.2a.69 .69 0 0 1 .5 .7 .69 .69 0 0 1-.5 .6l-.2-.2-.1-.3zM276.3 52.7l.4-1.3 .4 1.3"/>
<path d="M276.4 52.4h.6M298.4 58.4h.6l.1-.2-.1-.3-.6-.2v1.3M298.9 51.4l-.3 .9h.8M299.2 51.9v.8M299.7 51.3a1.47 1.47 0 0 1 0 1.9M300.3 57.8a.59 .59 0 0 0-.7 .6 .59 .59 0 0 0 .7 .6l.1-.5h-.3M130.1 70.4h.7M130.1 67.9h.7M130.4 67.9v1.3M130.4 70.4v1.3M131.5 67.9l-.3 .8h.8M131.8 68.3v.9"/>
<path d="M131.8 70.4h-.6v.7l.4-.2 .3 .3v.3l-.3 .2-.4-.1M133.5 75.5h.7M133.7 73h.7M133.8 75.5v1.3M134 73v1.3M134 60.3h.7M134.4 60.3v1.3M134.5 75.5h.8l-.5 1.3M135 62.8h.7M135 65.4h.7M135.1 60.6l.4-.3v1.3M135.1 61.6h.7"/>
<path d="M135.3 73h-.2a.79 .79 0 0 0-.1 1.3l.4-.2v-.5l-.4-.1-.3 .2M135.3 62.8v1.3M135.3 65.4v1.2M136 65.4h.8l-.4 .4 .3 .2v.6h-.5l-.2-.1M136.1 63l.5-.2 .2 .4-.1 .2-.7 .7h.8M140.4 60.9h.6l.1-.2v-.3l-.7-.1v1.3M140.9 66h.6l.1-.2v-.3l-.7-.1v1.2M142 63.5l.6-.1 .2-.1-.1-.3-.7-.2v1.3M142.4 60.4a.51 .51 0 0 0-.6 0 .51 .51 0 0 0-.2 .6l.3 .5 .5-.1M142.9 65.5a.51 .51 0 0 0-.6 0 .51 .51 0 0 0-.2 .6l.2 .5 .6-.1M143.6 78.1v1.2l-.8-1.2v1.2M144 78.1h.7"/>
<path d="M144 63a.6 .6 0 0 0-.8 .4 .6 .6 0 0 0 .6 .7l.2-.1M144.3 78.1v1.2M145.3 78.6l-.2-.1v-.3l.5-.1 .1 .1v.3l-.5 .2-.1 .2v.2l.2 .2h.3l.2-.2-.1-.4-.1-.1M152.1 73.6l.7-.1v-.4l-.2-.1h-.5v1.3M152.1 76.2l.7-.1v-.4l-.2-.2h-.5v1.3M152.1 78.7l.7-.1v-.4l-.2-.1h-.5v1.2M152.1 68.6l.7-.1v-.5l-.2-.1h-.5v1.3M152.1 71.1l.7-.1v-.4l-.2-.2h-.5v1.3M264.3 60.6l.4-.3v1.3M264.3 61.6h.7M288.6 70.4l.8 1.3M288.6 73l.8 1.3"/>
<path d="M288.8 67.9v1l.2 .3 .4-.1 .1-.2v-1M288.8 65.4v1l.2 .2h.4l.1-.2v-1M288.8 75.5v1.1l.3 .2 .3-.1 .2-.1v-1.1M289.4 70.4l-.8 1.3M289.4 73l-.8 1.3M289.6 78.1v1l.2 .2h.2l.3-.2v-1M289.9 70.4a.64 .64 0 0 1 .8 .7 .64 .64 0 0 1-.8 .6zM289.9 73a.64 .64 0 0 1 .8 .6 .64 .64 0 0 1-.8 .7zM290.1 67.9v1.3h.6M290.1 65.4v1.2h.6M290.1 75.5v1.3h.7M290.9 78.1v1.2h.6"/>
<path d="M291.1 67.9v1.3h.6M291.1 70.8l.4-.4v1.3M291.1 65.4v1.2h.6M291.1 71.7h.7M291.2 75.5v1.3h.6M291.2 73.1l.2-.1a.67 .67 0 0 1 .5 .6 .67 .67 0 0 1-.5 .7l-.3-.5zM291.9 78.1v1.2h.6M297.6 78.7h.6l.1-.2-.1-.3-.6-.1v1.2M297.9 60.9l.7-.1v-.4l-.7-.1v1.3M298.6 76.2l.6-.1 .1-.1-.1-.3-.6-.2v1.3M298.9 73.6h.6l.1-.2-.1-.3-.6-.1v1.3M299.5 66h.6v-.5l-.6-.1v1.2"/>
<path d="M299.5 63.5l.6-.1v-.4l-.6-.2v1.3M299.5 68.6l.6-.1v-.5l-.6-.1v1.3M299.5 71.1h.6v-.5l-.6-.2v1.3M299.5 78.1a.59 .59 0 0 0-.7 .6 .59 .59 0 0 0 .7 .6l.1-.5h-.3M299.9 60.4a.59 .59 0 0 0-.7 .5 .59 .59 0 0 0 .7 .6v-.5h-.2M300.5 75.6a.59 .59 0 0 0-.7 .6 .59 .59 0 0 0 .7 .5l.1-.4h-.3M300.8 73.1a.59 .59 0 0 0-.7 .5 .59 .59 0 0 0 .7 .6l.1-.5h-.3M301.4 65.4a.59 .59 0 0 0-.7 .6 .59 .59 0 0 0 .7 .6v-.5h-.2M301.4 62.9a.59 .59 0 0 0-.7 .6 .59 .59 0 0 0 .7 .5v-.4h-.2M301.4 68a.59 .59 0 0 0-.7 .6 .59 .59 0 0 0 .7 .5v-.5h-.2M301.4 70.5a.59 .59 0 0 0-.7 .6 .59 .59 0 0 0 .7 .6v-.5h-.2M133.7 85.7h.7"/>
<path d="M134.8 86l.4-.3v1.3M134.8 87h.7M134.8 88.6l.4-.4v1.3M134.8 89.5h.8M134.9 83.5l.4-.4v1.3M134.9 84.4h.7M136 86l.4-.3v1.3M136 87h.7M136.1 88.4l.5-.2 .2 .4-.1 .2-.7 .7h.8M136.2 83.3l.2-.2a.67 .67 0 0 1 .5 .7 .67 .67 0 0 1-.5 .6l-.3-.5zM140.8 88.9l.7-.1v-.4l-.7-.2v1.3M142.1 88.8h.5l.2-.2-.1-.2-.6-.2v1.3h.5l.2-.1v-.3l-.3-.3"/>
<path d="M143.7 80.6v1.3l-.7-1.3v1.3M144.1 80.6h.7M144.5 80.6v1.3M145.9 81.2l-.2 .2-.4-.1-.1-.1v-.3l.2-.3h.3l.2 .3a.88 .88 0 0 1-.2 .9l-.4 .1M150.9 83.8h.6v-.5l-.6-.2v1.3M152.1 81.3l.7-.1v-.5l-.2-.1h-.5v1.3M289.2 88.2l.8 1.3M289.6 80.6l.8 1.3M289.7 83.1v1.1l.2 .2h.4l.1-.2v-1.1M289.7 85.7v1l.2 .3 .4-.1 .1-.2v-1M290 88.2l-.8 1.3M290.4 90.8l.8 1.2"/>
<path d="M290.4 80.6l-.8 1.3M290.5 88.2a.64 .64 0 0 1 .7 .7 .64 .64 0 0 1-.7 .6zM290.9 81.2h.4M291 83.1v1.3h.6M291 85.7v1.3h.6M291.2 90.8l-.8 1.2M291.5 80.6h-.6v1.3h.6M291.7 90.8a.64 .64 0 0 1 .8 .6 .64 .64 0 0 1-.8 .6zM291.7 88.6l.4-.4v1.3M291.7 89.5h.8M292 83.1v1.3h.6M292 81.3l.6-.1 .2-.2-.1-.3-.7-.1v1.3"/>
<path d="M292 85.7v1.3h.6M292.3 81.3l.5 .6M292.8 93.4l-.5-.1-.1 .1v.5l.6 .2v.2l-.2 .3-.5-.1M293.1 90.9l.1-.1a.67 .67 0 0 1 .5 .6 .67 .67 0 0 1-.5 .6l-.2-.2-.1-.2zM293.1 94.7h.9M294.3 93.3a.64 .64 0 0 1 .8 .6 .64 .64 0 0 1-.8 .7zM295.6 83.8l.7-.1v-.4l-.2-.2h-.5v1.3M295.6 88.9l.7-.1v-.4l-.2-.2h-.5v1.3M295.7 86.3h.6v-.5l-.6-.1v1.3M297.3 91.4h.6l.1-.2-.1-.3-.6-.1v1.2M297.5 83.2a.59 .59 0 0 0-.7 .6 .59 .59 0 0 0 .7 .6l.1-.5h-.2M297.5 88.3a.59 .59 0 0 0-.7 .6 .59 .59 0 0 0 .7 .5l.1-.4h-.2"/>
<path d="M297.6 85.8a.59 .59 0 0 0-.8 .5 .59 .59 0 0 0 .8 .6v-.5h-.2M297.6 81.3l.6-.1 .1-.2-.1-.3-.6-.1v1.3M299.2 90.8a.59 .59 0 0 0-.7 .6 .59 .59 0 0 0 .7 .6l.1-.5h-.3M299.5 80.7a.59 .59 0 0 0-.7 .6 .59 .59 0 0 0 .7 .5l.1-.5h-.3M299.9 95.8h.7M300.3 95.8v1.3M300.9 98.4h.7M300.9 95.8l.9 1.3M301.2 98.4v1.3M301.8 95.8l-.9 1.3M301.9 98.4l.8 1.3M302.7 98.4l-.8 1.3"/>
<path d="M303 96a.6 .6 0 0 0-.9 .4 .6 .6 0 0 0 .6 .7l.3-.1M303.2 99h.4M303.5 95.8v1.3M303.7 96.4l.5 .7M303.8 98.4h-.6v1.3h.6M304.2 95.8l-.7 .8M305.1 98.4v1.3l-.7-1.3v1.3M278.6 113.6v1.3l-.7-1.3v1.3M279 111.7l.7-.1v-.4l-.7-.1v1.3M279.9 113.8a.6 .6 0 0 0-.8 .4 .6 .6 0 0 0 .6 .7l.2-.1M281 111.2a.6 .6 0 0 0-.8 .4 .6 .6 0 0 0 .6 .8l.2-.2M281.7 116.8h.6l.1-.2-.1-.3-.6-.1v1.2"/>
<path d="M282.2 118.7v1.3l-.7-1.3v1.3M282.7 118.7h.7l-.4 .5 .4 .1v.5l-.2 .2-.5-.2M282.8 116.2h.8l-.4 .4 .4 .2-.1 .6h-.5l-.2-.1M283 107.3v-1.3l.4 .9 .4-.9v1.3M284.4 106a.64 .64 0 0 1 .7 .6 .64 .64 0 0 1-.7 .7zM284.5 108.5a.64 .64 0 0 1 .7 .7 .64 .64 0 0 1-.7 .6zM285.7 108.5v1.3M286.3 108.7l.3-.2a.44 .44 0 0 1 .5 .5v.6l-.3 .2h-.3a1.07 1.07 0 0 1-.2-1.1zM286.4 106.1a.6 .6 0 0 0-.8 .4 .6 .6 0 0 0 .6 .8l.2-.2M298.3 114.3l.7-.1v-.4l-.7-.2v1.3M299 111.7h.6l.2-.2-.1-.3-.7-.1v1.3M299.1 109.2l.7-.1v-.4l-.7-.2v1.3"/>
<path d="M299.6 114.2h.4M300.2 113.6h-.6v1.3M300.4 109.2h.4M300.5 119.4l.7-.1v-.5l-.7-.1v1.3M300.6 106.7l.6-.1 .1-.2v-.3l-.7-.1v1.3M300.8 100.9v1.3l-.7-1.3v1.3M301 108.5h-.6v1.3M301.3 116.8h.6l.1-.2-.1-.3-.6-.1v1.2M301.4 100.9v1.1l.3 .2 .3-.1 .1-.1v-1.1M301.7 103.5v1.2l-.8-1.2v1.2M301.8 119.3h.4M301.9 106.6h.4"/>
<path d="M302.3 103.5v1l.2 .2h.2l.3-.2v-1M302.4 118.7h-.6v1.3M302.5 106h-.6v1.3M302.5 116.8h.5M302.7 100.9v1.3h.7M303.1 116.2h-.6v1.2M303.6 103.5v1.2h.6M303.8 100.9v1.3h.6M304.6 103.5v1.2h.6M119.4 149.5l.4-.3v1.3M119.4 150.5h.8M119.6 146.8l.1-.2a.67 .67 0 0 1 .5 .7 .67 .67 0 0 1-.5 .6l-.2-.2-.1-.3z"/>
<path d="M126.4 144.2l.4-1.3 .5 1.3M126.5 143.8h.6M131 152.4l.6-.1 .1-.4-.7-.2v1.3M131.8 156.8a.64 .64 0 0 1 .7 .6 .64 .64 0 0 1-.7 .7zM132.3 152.3h.4M132.9 154.3v1.2h.6M132.9 151.7h-.6v1.3h.6M133 157.4h.5M133.7 156.8h-.7v1.3h.7M133.9 154.3v1.2M134.1 154.8l.5 .7M134.6 154.3l-.7 .7"/>
<path d="M137.3 159.3v1.3l-.7-1.3v1.3M138.7 159.5a.6 .6 0 0 0-.9 .4 .6 .6 0 0 0 .6 .7l.3-.1M139.6 147.3l.6-.1v-.4l-.6-.2v1.3M139.6 149.8l.6-.1v-.4l-.6-.1v1.3M140.8 147.3h.4M140.8 149.8h.4M141.2 155l.5-.1v-.3l-.5-.1v.9M141.4 146.6h-.6v1.3h.6M141.4 149.2h-.6v1.3h.6M142.1 154.9h.3M142.6 154.5h-.5v.9h.5M142.9 154.6l.4-.1 .1 .2-.5 .7h.5"/>
<path d="M143.4 160h.4M144 159.3h-.6v1.3h.6M144 157.5l.4-.1v-.3l-.4-.1v.9M144.4 159.7l.4-.4v1.3M144.9 157.4h.3M145.3 157h-.4v.9h.4M149 142.8l-.3 .9h.8M149.3 143.3v.9M149.9 142.7a1.47 1.47 0 0 1 0 1.9M299.3 153a.64 .64 0 0 1 .8 .6 .64 .64 0 0 1-.8 .7zM129.2 167a.64 .64 0 0 1 .8 .6 .64 .64 0 0 1-.8 .6zM129.2 169.5a.64 .64 0 0 1 .8 .6 .64 .64 0 0 1-.8 .7z"/>
<path d="M129.2 177.1a.64 .64 0 0 1 .8 .7 .64 .64 0 0 1-.8 .6zM129.2 164.4a.64 .64 0 0 1 .8 .7 .64 .64 0 0 1-.8 .6zM129.2 172a.64 .64 0 0 1 .8 .7 .64 .64 0 0 1-.8 .6zM129.2 174.6a.64 .64 0 0 1 .8 .6 .64 .64 0 0 1-.8 .7zM130.4 167h.8l-.5 .4 .4 .2v.5l-.2 .1-.5-.1M130.4 177.1h.8l-.5 1.3M130.4 164.6l.5-.2 .3 .4-.1 .2-.7 .7h.8M130.7 169.5l-.3 .8h.8M131 174.6h-.2a.79 .79 0 0 0-.1 1.3l.4-.2v-.5l-.4-.1-.3 .2M131 169.9v.9M131.1 172h-.6l-.1 .7 .2-.2 .5 .2v.5l-.2 .1-.5-.1M133 179.8l.2-.1a.69 .69 0 0 1 .4 .6 .69 .69 0 0 1-.4 .6l-.2-.1-.1-.3z"/>
<path d="M138.2 162a.6 .6 0 0 0-.9 .4 .6 .6 0 0 0 .6 .8l.3-.2M142.1 165.1l.7-.1v-.4l-.7-.2v1.3M142.1 167.6l.7-.1v-.4l-.7-.1v1.2M142.1 162.5l.7-.1v-.4l-.7-.1v1.3M142.1 160l.7-.1v-.4l-.7-.2v1.3M142.1 170.2l.7-.1v-.5l-.7-.1v1.3M142.1 172.7l.7-.1v-.4l-.7-.2v1.3M143.3 177.8l.6-.1 .1-.1v-.3l-.7-.2v1.3M143.3 175.2h.6l.1-.2v-.3l-.7-.1v1.3M143.4 165h.4M143.4 167.6h.4M143.4 162.5h.4"/>
<path d="M143.4 170.1h.4M143.4 172.7h.4M144 164.4h-.6v1.3h.6M144 167h-.6v1.2h.6M144 161.9h-.6v1.3h.6M144 169.5h-.6v1.3h.6M144 172h-.6v1.3h.6M144.4 164.8l.4-.4v1.3M144.4 167.3l.4-.3v1.2M144.4 162.2l.4-.3v1.3M144.4 169.9l.4-.4v1.3M144.4 172.4l.4-.4v1.3"/>
<path d="M144.4 165.7h.8M144.4 168.2h.8M144.4 163.2h.8M144.4 160.6h.8M144.4 170.8h.8M144.4 173.3h.8M144.6 177.7h.4M144.6 175.2h.4M145.2 177.1h-.6v1.3h.6M145.2 179.7h-.6v1.2h.6M145.2 174.6h-.6v1.3h.6M131.6 180l.4-.3v1.2"/>
<path d="M131.6 180.9h.8M143.3 180.3h.6l.1-.2v-.3l-.7-.1v1.2M144.6 180.3h.4"/>
</g>
<g fill="none" stroke="#840000" stroke-width=".25">
<path d="M92.9 57.3h11.9l.6 1.2-.6 1.1h-11.9zM93.2 59.9h11.6l.6 1.1-.6 1.1h-11.6zM329.6 57.3h12.9v2.3h-12.9l-.7-1.1zM329.6 59.9h13.4v2.2h-13.4l-.7-1.1zM90.7 72.6h14.1l.6 1.1-.6 1.1h-14.1zM90.7 77.7h14.1l.6 1.1-.6 1.1h-14.1zM90.8 75.1h14l.6 1.1-.6 1.2h-14zM91.9 62.4h12.9l.6 1.1-.6 1.2h-12.9zM91.9 65h12.9l.6 1.1-.6 1.1h-12.9zM94.1 70h10.7l.6 1.2-.6 1.1h-10.7zM94.1 67.5h10.7l.6 1.1-.6 1.1h-10.7zM329.6 67.5h11.9v2.2h-11.9l-.7-1.1z"/>
<path d="M329.6 62.4h11.9v2.3h-11.9l-.7-1.2zM329.6 65h11.9v2.2h-11.9l-.7-1.1zM329.6 70h11.9v2.3h-11.9l-.7-1.1zM329.6 72.6h9.6v2.2h-9.6l-.7-1.1zM329.6 75.1h9.9v2.3h-9.9l-.7-1.2zM329.6 77.7h12v2.2h-12l-.7-1.1zM90.8 80.2h14l.6 1.1-.6 1.1h-14zM91.1 82.7h13.7l.6 1.2-.6 1.1h-13.7zM92.5 85.3h12.3l.6 1.1-.6 1.1h-12.3zM96.5 87.8h8.3l.6 1.1-.6 1.2h-8.3zM172.1 87.8h9.5v2.3h-9.5l-.7-1.2zM329.6 80.2h7.2v2.2h-7.2l-.7-1.1z"/>
<path d="M329.6 82.7h13.6v2.3h-13.6l-.7-1.1zM329.6 85.3h12.3v2.2h-12.3l-.7-1.1zM329.6 90.4h11.9v2.2h-11.9l-.7-1.1zM329.6 87.8h13.6v2.3h-13.6l-.7-1.2zM112.6 118.3h10l.6 1.1-.6 1.1h-10zM146 115.6h2.6v10.2h-2.6zM157.5 116.2h5.1v8.9h-5.1zM329.6 103.1h11.1v2.2h-11.1l-.7-1.1zM329.6 105.6h9v2.2h-9l-.7-1.1zM329.6 108.1h9v2.3h-9l-.7-1.1zM329.6 110.7h10.5v2.2h-10.5l-.7-1.1zM329.6 115.8h9v2.2h-9l-.7-1.1z"/>
<path d="M329.6 118.3h9v2.2h-9l-.7-1.1zM329.6 113.2h10v2.3h-10l-.7-1.2zM113 120.8h9.6l.6 1.2-.6 1.1h-9.6zM172.1 156.4h10.7v2.2h-10.7l-.7-1.1zM172.1 158.9h11.5v2.3h-11.5l-.7-1.1zM172.1 151.3h9v2.3h-9l-.7-1.2zM172.1 153.9h9.2v2.2h-9.2l-.7-1.1zM172.1 148.8h11.2v2.2h-11.2l-.7-1.1zM172.1 146.2h10.8v2.3h-10.8l-.7-1.1zM301 149.9h7.6l3.8-3.8h1.3v1.3h2.5l1.3-1.3h12.7v24.1h-29.2zM326.4 146.1v-1.3h-35.6v33h35.6v-7.6M83.8 164h12.1l.6 1.1-.6 1.2h-12.1z"/>
<path d="M86.7 166.6h9.2l.6 1.1-.6 1.1h-9.2zM358.3 207.1h2.2v10.7l-1.1 .7-1.1-.7zM367.2 207.1h2.2v10.7l-1.1 .7-1.1-.7z"/>
</g>
<g fill="#840000" stroke="#840000" stroke-width=".18">
<path d="M302.3 168.3h2.5v1.3h-2.5z"/>
<path d="M302.3 165.8h2.5v1.2h-2.5z"/>
<path d="M302.3 163.2h2.5v1.3h-2.5z"/>
<path d="M302.3 160.7h2.5v1.3h-2.5z"/>
<path d="M302.3 158.2h2.5v1.2h-2.5z"/>
<path d="M302.3 155.6h2.5v1.3h-2.5z"/>
<path d="M302.3 153.1h2.5v1.2h-2.5z"/>
<path d="M302.3 150.5h2.5v1.3h-2.5z"/>
<circle cx="161.3" cy="120.7" r=".25"/>
</g>
<g fill="none" stroke="#008400" stroke-width=".18">
<path d="M240 58.5h10.2M240 57.2v2.5M247.6 58.5v2.5h2.6M123.2 119.4h2.5M130.8 119.4h11.4M154.9 118.1v-3.8h-22.8v5.1M123.2 122h2.5M130.8 122h11.4M132.1 122v5h22.8v-3.8M102.9 146.1v3.8h2.5M102.9 147.4h2.5M254 149.9v2.5"/>
<path d="M254 157.5v2.6M254 158.8h33M254 151.2h5.1v20.3M266.7 153.7h20.3M266.7 156.2h20.3M266.7 151.2h20.3M96.5 165.1h8.9M104.1 167.7h1.3M266.7 161.3h20.3M266.7 166.4h20.3M266.7 168.9h20.3M266.7 171.5h20.3"/>
</g>
<g fill="#008400" stroke="#008400" stroke-width=".25">
<circle cx="254" cy="151.2" r=".51"/>
<circle cx="259.1" cy="156.2" r=".51"/>
<circle cx="259.1" cy="166.4" r=".51"/>
<circle cx="254" cy="158.8" r=".51"/>
<circle cx="259.1" cy="151.2" r=".51"/>
<circle cx="259.1" cy="161.3" r=".51"/>
<circle cx="247.7" cy="58.5" r=".51"/>
<circle cx="259.1" cy="153.7" r=".51"/>
<circle cx="132.1" cy="119.4" r=".51"/>
<circle cx="132.1" cy="122" r=".51"/>
<circle cx="259.1" cy="168.9" r=".51"/>
<circle cx="240" cy="58.5" r=".51"/>
<circle cx="102.9" cy="147.4" r=".51"/>
</g>
<g fill="none" stroke="#000084" stroke-width=".18">
<path d="M170.8 57.8l1.3 1.3M172.1 57.8l-1.3 1.3M170.8 75.6l1.3 1.2M170.8 60.4l1.3 1.2M170.8 62.9l1.3 1.2M170.8 65.5l1.3 1.2M170.8 78.2l1.3 1.2M170.8 73.1l1.3 1.2M170.8 70.5l1.3 1.3M170.8 68l1.3 1.2M172.1 75.6l-1.3 1.2M172.1 60.4l-1.3 1.2"/>
<path d="M172.1 62.9l-1.3 1.2M172.1 65.5l-1.3 1.2M172.1 78.2l-1.3 1.2M172.1 73.1l-1.3 1.2M172.1 70.5l-1.3 1.3M172.1 68l-1.3 1.2M249.6 78.2l1.2 1.2M249.6 75.6l1.2 1.2M249.6 70.5l1.2 1.3M249.6 73.1l1.2 1.2M249.6 68l1.2 1.2M249.6 65.5l1.2 1.2"/>
<path d="M250.8 78.2l-1.2 1.2M250.8 75.6l-1.2 1.2M250.8 70.5l-1.2 1.3M250.8 73.1l-1.2 1.2M250.8 68l-1.2 1.2M250.8 65.5l-1.2 1.2M170.8 83.2l1.3 1.3M170.8 80.7l1.3 1.2M172.1 83.2l-1.3 1.3M172.1 80.7l-1.3 1.2M249.6 85.8l1.2 1.2M249.6 83.2l1.2 1.3"/>
<path d="M249.6 80.7l1.2 1.2M249.6 95.9l1.2 1.3M249.6 98.5l1.2 1.2M249.6 90.9l1.2 1.2M249.6 93.4l1.2 1.2M249.6 88.3l1.2 1.2M250.8 85.8l-1.2 1.2M250.8 83.2l-1.2 1.3M250.8 80.7l-1.2 1.2M250.8 95.9l-1.2 1.3M250.8 98.5l-1.2 1.2M250.8 90.9l-1.2 1.2"/>
<path d="M250.8 93.4l-1.2 1.2M250.8 88.3l-1.2 1.2M249.6 101l1.2 1.2M249.6 103.6l1.2 1.2M249.6 106.1l1.2 1.2M249.6 108.6l1.2 1.3M249.6 111.2l1.2 1.2M249.6 113.7l1.2 1.2M249.6 118.8l1.2 1.2M249.6 116.3l1.2 1.2M250.8 101l-1.2 1.2M250.8 103.6l-1.2 1.2"/>
<path d="M250.8 106.1l-1.2 1.2M250.8 108.6l-1.2 1.3M250.8 111.2l-1.2 1.2M250.8 113.7l-1.2 1.2M250.8 118.8l-1.2 1.2M250.8 116.3l-1.2 1.2M104.8 159.4l1.2 1.3M104.8 156.9l1.2 1.2M104.8 154.4l1.2 1.2M106 159.4l-1.2 1.3M106 156.9l-1.2 1.2M106 154.4l-1.2 1.2"/>
<path d="M104.8 162l1.2 1.2M104.8 179.8l1.2 1.2M104.8 177.2l1.2 1.2M104.8 174.7l1.2 1.2M104.8 172.1l1.2 1.3M104.8 169.6l1.2 1.2M106 162l-1.2 1.2M106 179.8l-1.2 1.2M106 177.2l-1.2 1.2M106 174.7l-1.2 1.2M106 172.1l-1.2 1.3M106 169.6l-1.2 1.2"/>
<path d="M170.8 174.7l1.3 1.2M170.8 162l1.3 1.2M170.8 164.5l1.3 1.2M170.8 179.8l1.3 1.2M170.8 177.2l1.3 1.2M170.8 172.1l1.3 1.3M170.8 169.6l1.3 1.2M170.8 167.1l1.3 1.2M172.1 174.7l-1.3 1.2M172.1 162l-1.3 1.2M172.1 179.8l-1.3 1.2M172.1 164.5l-1.3 1.2"/>
<path d="M172.1 169.6l-1.3 1.2M172.1 172.1l-1.3 1.3M172.1 177.2l-1.3 1.2M172.1 167.1l-1.3 1.2"/>
</g>
<use href="#words"/>
</svg>
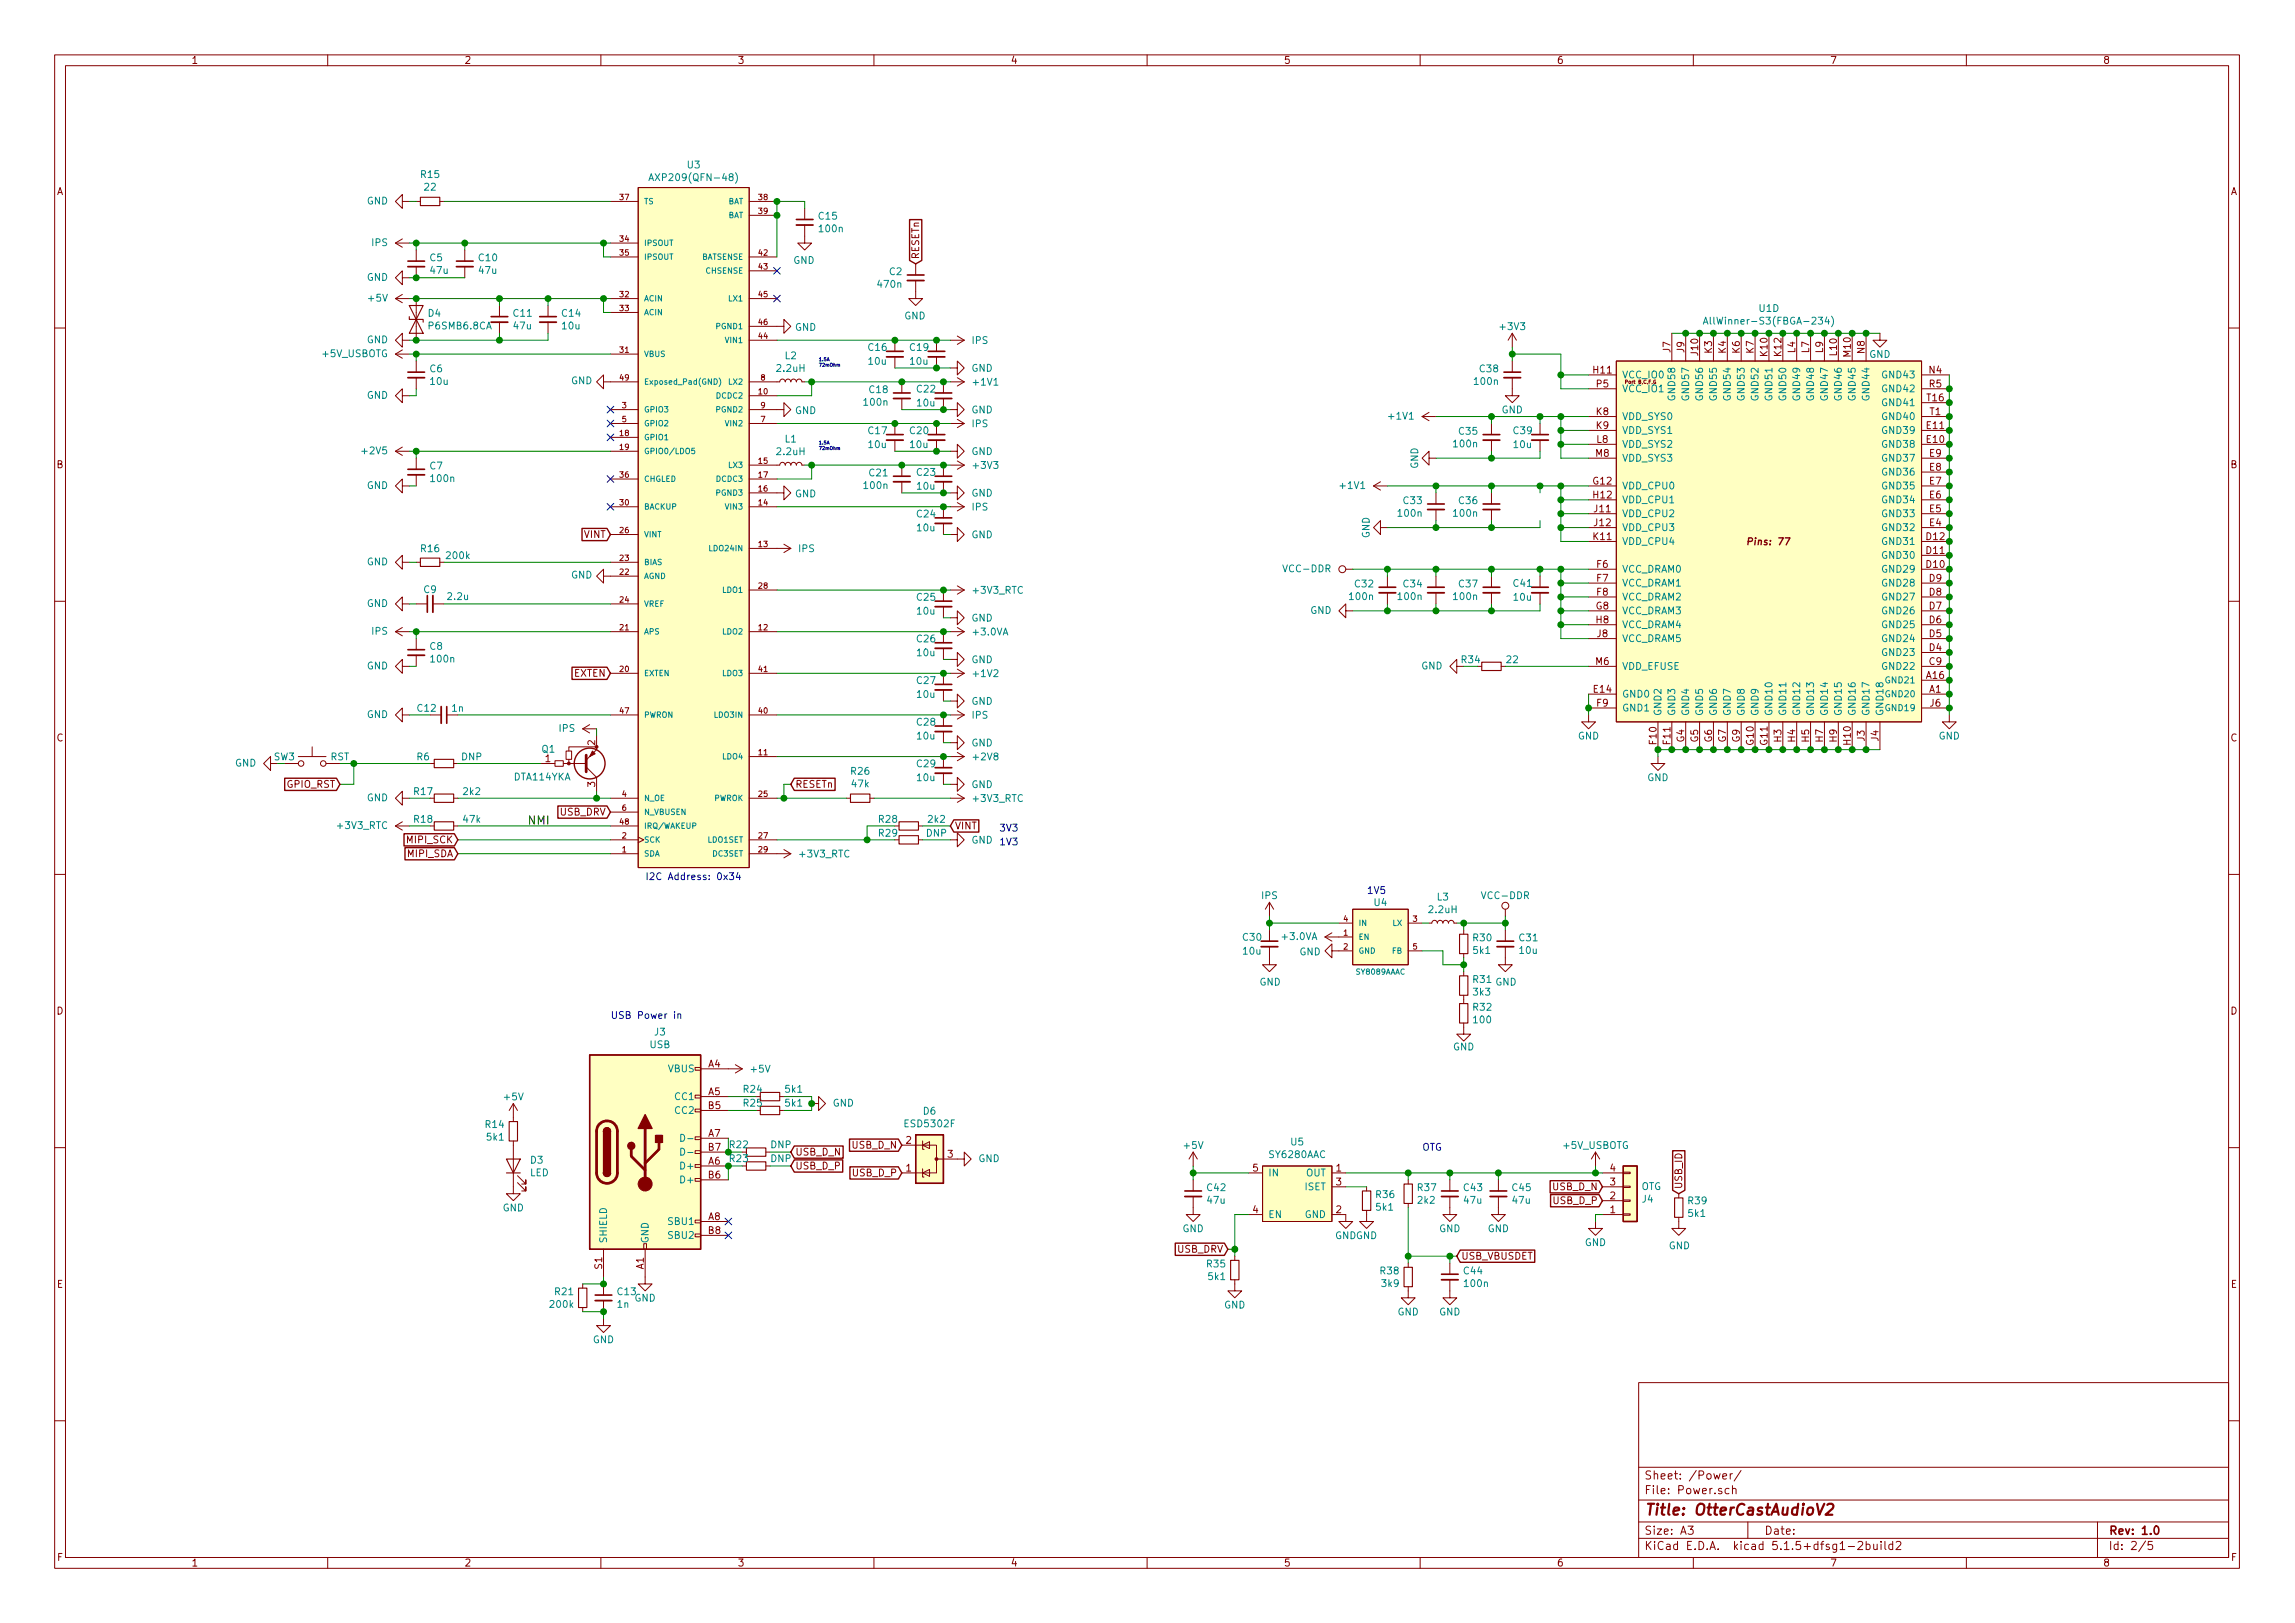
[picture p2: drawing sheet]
<svg xmlns="http://www.w3.org/2000/svg" width="420mm" height="297mm" viewBox="0 0 420 297" stroke-linecap="round" stroke-linejoin="round" font-family="sans-serif">
<defs><g id="words">
<text font-size="2.8" fill="#840000" x="301" y="277.3">Title: OtterCastAudioV2</text>
<text font-size="2.1" x="96.5" y="150.9">NMI</text>
<g font-size="2.1" fill="#840000">
<text x="301" y="273.5">File: Power.sch</text>
<text x="301" y="270.8">Sheet: /Power/</text>
<text x="301" y="280.9">Size: A3</text>
<text x="323" y="280.9">Date:</text>
<text x="386" y="280.9">Rev: 1.0</text>
<text x="301" y="283.7">KiCad E.D.A. kicad 5.1.5+dfsg1-2build2</text>
<text x="386" y="283.7">Id: 2/5</text>
</g>
<g font-size="1.8" fill="#840000">
<text x="35" y="11.7">1</text>
<text x="85" y="11.7">2</text>
<text x="135" y="11.7">3</text>
<text x="185" y="11.7">4</text>
<text x="235" y="11.7">5</text>
<text x="285" y="11.7">6</text>
<text x="335" y="11.7">7</text>
<text x="385" y="11.7">8</text>
<text x="10.4" y="35.7">A</text>
<text x="408.4" y="35.7">A</text>
<text x="168.3" y="47.5" transform="rotate(-90 168.3 47.5)">RESETn</text>
<text x="305.8" y="64.5" transform="rotate(-90 305.8 64.5)">J7</text>
<text x="308.4" y="64.5" transform="rotate(-90 308.4 64.5)">J9</text>
<text x="310.9" y="65" transform="rotate(-90 310.9 65)">J10</text>
<text x="313.4" y="64.7" transform="rotate(-90 313.4 64.7)">K3</text>
<text x="316" y="64.7" transform="rotate(-90 316 64.7)">K4</text>
<text x="318.5" y="64.7" transform="rotate(-90 318.5 64.7)">K6</text>
<text x="321.1" y="64.7" transform="rotate(-90 321.1 64.7)">K7</text>
<text x="323.6" y="65.2" transform="rotate(-90 323.6 65.2)">K10</text>
<text x="326.1" y="65.2" transform="rotate(-90 326.1 65.2)">K12</text>
<text x="328.7" y="64.6" transform="rotate(-90 328.7 64.6)">L4</text>
<text x="331.2" y="64.6" transform="rotate(-90 331.2 64.6)">L7</text>
<text x="333.8" y="64.6" transform="rotate(-90 333.8 64.6)">L9</text>
<text x="336.3" y="65.1" transform="rotate(-90 336.3 65.1)">L10</text>
<text x="338.8" y="65.2" transform="rotate(-90 338.8 65.2)">M10</text>
<text x="341.4" y="64.7" transform="rotate(-90 341.4 64.7)">N8</text>
<text x="291.7" y="68.4">H11</text>
<text x="292.3" y="70.9">P5</text>
<text x="353.2" y="68.4">N4</text>
<text x="353.2" y="70.9">R5</text>
<text x="292.3" y="76">K8</text>
<text x="352.8" y="73.4">T16</text>
<text x="353.3" y="76">T1</text>
<text x="292.2" y="83.6">M8</text>
<text x="292.3" y="78.5">K9</text>
<text x="292.4" y="81.1">L8</text>
<text x="352.8" y="81.1">E10</text>
<text x="352.8" y="78.5">E11</text>
<text x="353.3" y="83.6">E9</text>
<text x="10.4" y="85.7">B</text>
<text x="291.7" y="88.7">G12</text>
<text x="353.3" y="88.7">E7</text>
<text x="353.3" y="86.1">E8</text>
<text x="408.4" y="85.7">B</text>
<text x="291.7" y="91.2">H12</text>
<text x="291.9" y="93.8">J11</text>
<text x="353.3" y="93.8">E5</text>
<text x="353.3" y="91.2">E6</text>
<text x="106.9" y="98.5">VINT</text>
<text x="291.7" y="98.8">K11</text>
<text x="291.9" y="96.3">J12</text>
<text x="320.5" y="99.8">Pins: 77</text>
<text x="352.7" y="101.4">D11</text>
<text x="352.7" y="98.8">D12</text>
<text x="353.3" y="96.3">E4</text>
<text x="292.4" y="103.9">F6</text>
<text x="292.4" y="106.5">F7</text>
<text x="352.7" y="103.9">D10</text>
<text x="353.2" y="106.5">D9</text>
<text x="292.2" y="111.5">G8</text>
<text x="292.4" y="109">F8</text>
<text x="353.2" y="111.5">D7</text>
<text x="353.2" y="109">D8</text>
<text x="292.3" y="114.1">H8</text>
<text x="292.4" y="116.6">J8</text>
<text x="353.2" y="119.2">D4</text>
<text x="353.2" y="116.6">D5</text>
<text x="353.2" y="114.1">D6</text>
<text x="105.1" y="123.9">EXTEN</text>
<text x="292.2" y="121.7">M6</text>
<text x="352.7" y="124.2">A16</text>
<text x="353.2" y="121.7">C9</text>
<text x="291.8" y="126.8">E14</text>
<text x="292.4" y="129.3">F9</text>
<text x="353.2" y="126.8">A1</text>
<text x="353.4" y="129.3">J6</text>
<text x="10.4" y="135.7">C</text>
<text x="109" y="136.4" transform="rotate(-90 109 136.4)">2</text>
<text x="303.3" y="136.2" transform="rotate(-90 303.3 136.2)">F10</text>
<text x="305.8" y="136.2" transform="rotate(-90 305.8 136.2)">F11</text>
<text x="308.4" y="135.8" transform="rotate(-90 308.4 135.8)">G4</text>
<text x="310.9" y="135.8" transform="rotate(-90 310.9 135.8)">G5</text>
<text x="313.4" y="135.8" transform="rotate(-90 313.4 135.8)">G6</text>
<text x="316" y="135.8" transform="rotate(-90 316 135.8)">G7</text>
<text x="318.5" y="135.8" transform="rotate(-90 318.5 135.8)">G9</text>
<text x="321.1" y="136.3" transform="rotate(-90 321.1 136.3)">G10</text>
<text x="323.6" y="136.3" transform="rotate(-90 323.6 136.3)">G11</text>
<text x="326.1" y="135.8" transform="rotate(-90 326.1 135.8)">H3</text>
<text x="328.7" y="135.8" transform="rotate(-90 328.7 135.8)">H4</text>
<text x="331.2" y="135.8" transform="rotate(-90 331.2 135.8)">H5</text>
<text x="333.8" y="135.8" transform="rotate(-90 333.8 135.8)">H7</text>
<text x="336.3" y="135.8" transform="rotate(-90 336.3 135.8)">H9</text>
<text x="338.8" y="136.3" transform="rotate(-90 338.8 136.3)">H10</text>
<text x="341.4" y="135.6" transform="rotate(-90 341.4 135.6)">J3</text>
<text x="343.9" y="135.6" transform="rotate(-90 343.9 135.6)">J4</text>
<text x="408.4" y="135.7">C</text>
<text x="99.8" y="139.5">1</text>
<text x="52.5" y="144.2">GPIO_RST</text>
<text x="102.5" y="149.3">USB_DRV</text>
<text x="109" y="144" transform="rotate(-90 109 144)">3</text>
<text x="145.6" y="144.2">RESETn</text>
<text x="74.7" y="154.3">MIPI_SCK</text>
<text x="174.8" y="151.8">VINT</text>
<text x="74.7" y="156.9">MIPI_SDA</text>
<text x="10.4" y="185.7">D</text>
<text x="408.4" y="185.7">D</text>
<text x="129.7" y="195.4">A4</text>
<text x="129.7" y="200.4">A5</text>
<text x="129.7" y="203">B5</text>
<text x="136.2" y="202.5">R25</text>
<text x="129.7" y="208.1">A7</text>
<text x="165.9" y="209.3">2</text>
<text x="129.7" y="213.1">A6</text>
<text x="129.7" y="215.7">B6</text>
<text x="129.7" y="210.6">B7</text>
<text x="145.6" y="214">USB_D_P</text>
<text x="145.6" y="211.5">USB_D_N</text>
<text x="156.1" y="210.2">USB_D_N</text>
<text x="156.2" y="215.3">USB_D_P</text>
<text x="165.9" y="214.4">1</text>
<text x="173.5" y="211.9">3</text>
<text x="229.4" y="214.4">5</text>
<text x="244.6" y="214.4">1</text>
<text x="294.8" y="214.4">4</text>
<text x="244.6" y="217">3</text>
<text x="284.3" y="217.8">USB_D_N</text>
<text x="284.4" y="220.4">USB_D_P</text>
<text x="294.8" y="219.5">2</text>
<text x="294.8" y="217">3</text>
<text x="308" y="217.7" transform="rotate(-90 308 217.7)">USB_ID</text>
<text x="129.7" y="223.3">A8</text>
<text x="129.7" y="225.8">B8</text>
<text x="229.4" y="222">4</text>
<text x="244.6" y="222">2</text>
<text x="294.8" y="222">1</text>
<text x="110.2" y="232.2" transform="rotate(-90 110.2 232.2)">S1</text>
<text x="117.9" y="232.3" transform="rotate(-90 117.9 232.3)">A1</text>
<text x="215.5" y="229.3">USB_DRV</text>
<text x="267.5" y="230.5">USB_VBUSDET</text>
<text x="10.4" y="235.7">E</text>
<text x="408.4" y="235.7">E</text>
<text x="10.5" y="285.7">F</text>
<text x="35" y="286.7">1</text>
<text x="85" y="286.7">2</text>
<text x="135" y="286.7">3</text>
<text x="185" y="286.7">4</text>
<text x="235" y="286.7">5</text>
<text x="285" y="286.7">6</text>
<text x="335" y="286.7">7</text>
<text x="385" y="286.7">8</text>
<text x="408.5" y="285.7">F</text>
</g>
<g font-size="1.8" fill="#008484">
<text x="77.1" y="32.6">R15</text>
<text x="77.8" y="34.9">22</text>
<text x="120" y="33.1">AXP209(QFN-48)</text>
<text x="125.9" y="30.8">U3</text>
<text x="67.2" y="37.4">GND</text>
<text x="149.9" y="40.2">C15</text>
<text x="68.1" y="45">IPS</text>
<text x="78.7" y="47.8">C5</text>
<text x="87.7" y="47.8">C10</text>
<text x="150.1" y="42.5">100n</text>
<text x="67.2" y="51.4">GND</text>
<text x="78.9" y="50.1">47u</text>
<text x="87.8" y="50.1">47u</text>
<text x="145.2" y="48.3">GND</text>
<text x="160.8" y="52.7">470n</text>
<text x="162.9" y="50.4">C2</text>
<text x="67.5" y="55.2">+5V</text>
<text x="78.4" y="58">D4</text>
<text x="94.1" y="58">C11</text>
<text x="102.9" y="58">C14</text>
<text x="165.6" y="58.5">GND</text>
<text x="313.5" y="59.4">AllWinner-S3(FBGA-234)</text>
<text x="322.1" y="57.1">U1D</text>
<text x="59.1" y="65.4">+5V_USBOTG</text>
<text x="67.2" y="62.8">GND</text>
<text x="78.6" y="60.3">P6SMB6.8CA</text>
<text x="94.1" y="60.3">47u</text>
<text x="103" y="60.3">10u</text>
<text x="143.8" y="65.7">L2</text>
<text x="145.5" y="60.5">GND</text>
<text x="159" y="64.2">C16</text>
<text x="166.6" y="64.2">C19</text>
<text x="178" y="63">IPS</text>
<text x="274.8" y="60.4">+3V3</text>
<text x="342.2" y="65.5">GND</text>
<text x="78.7" y="68.1">C6</text>
<text x="78.9" y="70.4">10u</text>
<text x="104.5" y="70.3">GND</text>
<text x="142.3" y="68.1">2.2uH</text>
<text x="159.1" y="66.8">10u</text>
<text x="159.2" y="71.9">C18</text>
<text x="166.7" y="66.8">10u</text>
<text x="167.9" y="71.8">C22</text>
<text x="177.9" y="68">GND</text>
<text x="178.3" y="70.6">+1V1</text>
<text x="270.1" y="70.4">100n</text>
<text x="271" y="68.1">C38</text>
<text x="296.9" y="69.3">VCC_IO0</text>
<text x="296.9" y="71.8">VCC_IO1</text>
<text x="344.9" y="69.3">GND43</text>
<text x="344.9" y="71.8">GND42</text>
<text x="67.2" y="73">GND</text>
<text x="145.5" y="75.8">GND</text>
<text x="158.3" y="74.3">100n</text>
<text x="168" y="74.4">10u</text>
<text x="177.9" y="75.7">GND</text>
<text x="254.4" y="76.8">+1V1</text>
<text x="274.9" y="75.7">GND</text>
<text x="296.9" y="76.9">VDD_SYS0</text>
<text x="306.7" y="73" transform="rotate(-90 306.7 73)">GND58</text>
<text x="309.2" y="73" transform="rotate(-90 309.2 73)">GND57</text>
<text x="311.8" y="73" transform="rotate(-90 311.8 73)">GND56</text>
<text x="314.3" y="73" transform="rotate(-90 314.3 73)">GND55</text>
<text x="316.9" y="73" transform="rotate(-90 316.9 73)">GND54</text>
<text x="319.4" y="73" transform="rotate(-90 319.4 73)">GND53</text>
<text x="321.9" y="73" transform="rotate(-90 321.9 73)">GND52</text>
<text x="324.5" y="73" transform="rotate(-90 324.5 73)">GND51</text>
<text x="327" y="73" transform="rotate(-90 327 73)">GND50</text>
<text x="329.6" y="73" transform="rotate(-90 329.6 73)">GND49</text>
<text x="332.1" y="73" transform="rotate(-90 332.1 73)">GND48</text>
<text x="334.6" y="73" transform="rotate(-90 334.6 73)">GND47</text>
<text x="337.2" y="73" transform="rotate(-90 337.2 73)">GND46</text>
<text x="339.7" y="73" transform="rotate(-90 339.7 73)">GND45</text>
<text x="342.3" y="73" transform="rotate(-90 342.3 73)">GND44</text>
<text x="344.9" y="76.9">GND40</text>
<text x="344.9" y="74.3">GND41</text>
<text x="66.4" y="83.1">+2V5</text>
<text x="142.3" y="83.3">2.2uH</text>
<text x="143.8" y="81">L1</text>
<text x="159" y="79.5">C17</text>
<text x="159.1" y="82">10u</text>
<text x="166.6" y="79.5">C20</text>
<text x="166.7" y="82">10u</text>
<text x="177.9" y="83.3">GND</text>
<text x="178" y="78.2">IPS</text>
<text x="266.2" y="81.9">100n</text>
<text x="267.2" y="79.6">C35</text>
<text x="277.1" y="79.5">C39</text>
<text x="277.2" y="82">10u</text>
<text x="296.9" y="79.4">VDD_SYS1</text>
<text x="296.9" y="82">VDD_SYS2</text>
<text x="344.9" y="82">GND38</text>
<text x="344.9" y="79.4">GND39</text>
<text x="67.2" y="89.5">GND</text>
<text x="78.7" y="85.9">C7</text>
<text x="79" y="88.2">100n</text>
<text x="158.3" y="89.5">100n</text>
<text x="159.2" y="87.2">C21</text>
<text x="167.9" y="87.1">C23</text>
<text x="168" y="89.6">10u</text>
<text x="178.3" y="85.8">+3V3</text>
<text x="245.5" y="89.5">+1V1</text>
<text x="259.6" y="85.8" transform="rotate(-90 259.6 85.8)">GND</text>
<text x="296.9" y="89.6">VDD_CPU0</text>
<text x="296.9" y="84.5">VDD_SYS3</text>
<text x="344.9" y="89.6">GND35</text>
<text x="344.9" y="87">GND36</text>
<text x="344.9" y="84.5">GND37</text>
<text x="145.5" y="91">GND</text>
<text x="167.9" y="94.7">C24</text>
<text x="177.9" y="90.9">GND</text>
<text x="178" y="93.4">IPS</text>
<text x="256.1" y="94.6">100n</text>
<text x="257" y="92.3">C33</text>
<text x="266.2" y="94.6">100n</text>
<text x="267.2" y="92.3">C36</text>
<text x="296.9" y="92.1">VDD_CPU1</text>
<text x="296.9" y="94.7">VDD_CPU2</text>
<text x="344.9" y="94.7">GND33</text>
<text x="344.9" y="92.1">GND34</text>
<text x="77.1" y="101.1">R16</text>
<text x="146.2" y="101.1">IPS</text>
<text x="168" y="97.2">10u</text>
<text x="177.9" y="98.5">GND</text>
<text x="250.7" y="98.5" transform="rotate(-90 250.7 98.5)">GND</text>
<text x="296.9" y="97.2">VDD_CPU3</text>
<text x="296.9" y="99.7">VDD_CPU4</text>
<text x="344.9" y="99.7">GND31</text>
<text x="344.9" y="97.2">GND32</text>
<text x="67.2" y="103.5">GND</text>
<text x="81.9" y="102.3">200k</text>
<text x="104.5" y="105.9">GND</text>
<text x="235.2" y="104.7">VCC-DDR</text>
<text x="248.1" y="107.5">C32</text>
<text x="257" y="107.5">C34</text>
<text x="267.2" y="107.5">C37</text>
<text x="277.1" y="107.4">C41</text>
<text x="296.9" y="104.8">VCC_DRAM0</text>
<text x="296.9" y="107.4">VCC_DRAM1</text>
<text x="344.9" y="104.8">GND29</text>
<text x="344.9" y="102.3">GND30</text>
<text x="344.9" y="107.4">GND28</text>
<text x="67.2" y="111.1">GND</text>
<text x="77.6" y="108.5">C9</text>
<text x="82.1" y="109.8">2.2u</text>
<text x="167.9" y="109.9">C25</text>
<text x="168" y="112.5">10u</text>
<text x="177.9" y="113.8">GND</text>
<text x="178.3" y="108.7">+3V3_RTC</text>
<text x="239.9" y="112.4">GND</text>
<text x="247.2" y="109.8">100n</text>
<text x="256.1" y="109.8">100n</text>
<text x="266.2" y="109.8">100n</text>
<text x="277.2" y="109.9">10u</text>
<text x="296.9" y="109.9">VCC_DRAM2</text>
<text x="296.9" y="112.4">VCC_DRAM3</text>
<text x="344.9" y="112.4">GND26</text>
<text x="344.9" y="109.9">GND27</text>
<text x="68.1" y="116.2">IPS</text>
<text x="78.7" y="118.9">C8</text>
<text x="167.9" y="117.6">C26</text>
<text x="178.3" y="116.3">+3.0VA</text>
<text x="296.9" y="115">VCC_DRAM4</text>
<text x="296.9" y="117.5">VCC_DRAM5</text>
<text x="344.9" y="117.5">GND24</text>
<text x="344.9" y="115">GND25</text>
<text x="67.2" y="122.5">GND</text>
<text x="79" y="121.2">100n</text>
<text x="167.9" y="125.2">C27</text>
<text x="168" y="120.1">10u</text>
<text x="177.9" y="121.4">GND</text>
<text x="178.3" y="123.9">+1V2</text>
<text x="260.2" y="122.5">GND</text>
<text x="275.9" y="121.4">22</text>
<text x="296.9" y="122.6">VDD_EFUSE</text>
<text x="344.9" y="122.6">GND22</text>
<text x="344.9" y="120.1">GND23</text>
<text x="67.2" y="131.4">GND</text>
<text x="76.5" y="130.3">C12</text>
<text x="82.8" y="130.3">1n</text>
<text x="168" y="127.7">10u</text>
<text x="177.9" y="129">GND</text>
<text x="178" y="131.5">IPS</text>
<text x="296.9" y="127.7">GND0</text>
<text x="296.9" y="130.2">GND1</text>
<text x="304.2" y="131.1" transform="rotate(-90 304.2 131.1)">GND2</text>
<text x="306.7" y="131.1" transform="rotate(-90 306.7 131.1)">GND3</text>
<text x="309.2" y="131.1" transform="rotate(-90 309.2 131.1)">GND4</text>
<text x="311.8" y="131.1" transform="rotate(-90 311.8 131.1)">GND5</text>
<text x="314.3" y="131.1" transform="rotate(-90 314.3 131.1)">GND6</text>
<text x="316.9" y="131.1" transform="rotate(-90 316.9 131.1)">GND7</text>
<text x="319.4" y="131.1" transform="rotate(-90 319.4 131.1)">GND8</text>
<text x="321.9" y="131.1" transform="rotate(-90 321.9 131.1)">GND9</text>
<text x="324.5" y="131.1" transform="rotate(-90 324.5 131.1)">GND10</text>
<text x="327" y="131.1" transform="rotate(-90 327 131.1)">GND11</text>
<text x="329.6" y="131.1" transform="rotate(-90 329.6 131.1)">GND12</text>
<text x="332.1" y="131.1" transform="rotate(-90 332.1 131.1)">GND13</text>
<text x="334.6" y="131.1" transform="rotate(-90 334.6 131.1)">GND14</text>
<text x="337.2" y="131.1" transform="rotate(-90 337.2 131.1)">GND15</text>
<text x="339.7" y="131.1" transform="rotate(-90 339.7 131.1)">GND16</text>
<text x="342.3" y="131.1" transform="rotate(-90 342.3 131.1)">GND17</text>
<text x="344.8" y="131.1" transform="rotate(-90 344.8 131.1)">GND18</text>
<text x="99.2" y="137.8">Q1</text>
<text x="102.4" y="133.9">IPS</text>
<text x="167.9" y="132.8">C28</text>
<text x="168" y="135.3">10u</text>
<text x="177.9" y="136.6">GND</text>
<text x="288.9" y="135.3">GND</text>
<text x="354.9" y="135.3">GND</text>
<text x="43" y="140.3">GND</text>
<text x="60.5" y="139.2">RST</text>
<text x="76.4" y="139.2">R6</text>
<text x="84.5" y="139.2">DNP</text>
<text x="94.1" y="142.8">DTA114YKA</text>
<text x="155.9" y="141.8">R26</text>
<text x="167.9" y="140.4">C29</text>
<text x="168" y="143">10u</text>
<text x="178.3" y="139.2">+2V8</text>
<text x="301.6" y="143">GND</text>
<text x="67.2" y="146.6">GND</text>
<text x="75.8" y="145.5">R17</text>
<text x="84.9" y="145.5">2k2</text>
<text x="156" y="144.1">47k</text>
<text x="177.9" y="144.2">GND</text>
<text x="178.3" y="146.8">+3V3_RTC</text>
<text x="61.9" y="151.7">+3V3_RTC</text>
<text x="75.8" y="150.6">R18</text>
<text x="84.9" y="150.6">47k</text>
<text x="160.9" y="150.6">R28</text>
<text x="160.9" y="153.1">R29</text>
<text x="169.6" y="153.1">DNP</text>
<text x="170" y="150.6">2k2</text>
<text x="146.5" y="156.9">+3V3_RTC</text>
<text x="231" y="164.6">IPS</text>
<text x="251.6" y="165.8">U4</text>
<text x="261.7" y="167.1">2.2uH</text>
<text x="263.1" y="164.8">L3</text>
<text x="271.5" y="164.6">VCC-DDR</text>
<text x="227.6" y="172.2">C30</text>
<text x="234.8" y="172">+3.0VA</text>
<text x="269.7" y="172.3">R30</text>
<text x="278.2" y="172.3">C31</text>
<text x="227.7" y="174.7">10u</text>
<text x="237.9" y="174.8">GND</text>
<text x="269.7" y="179.9">R31</text>
<text x="269.8" y="174.6">5k1</text>
<text x="278.3" y="174.6">10u</text>
<text x="230.6" y="180.4">GND</text>
<text x="269.7" y="185">R32</text>
<text x="269.8" y="182.2">3k3</text>
<text x="273.8" y="180.4">GND</text>
<text x="119" y="191.8">USB</text>
<text x="119.9" y="189.5">J3</text>
<text x="269.9" y="187.3">100</text>
<text x="122.4" y="196.3">VBUS</text>
<text x="137.6" y="196.3">+5V</text>
<text x="266" y="192.2">GND</text>
<text x="92.4" y="201.4">+5V</text>
<text x="123.7" y="201.3">CC1</text>
<text x="123.7" y="203.9">CC2</text>
<text x="136.2" y="200">R24</text>
<text x="143.8" y="202.5">5k1</text>
<text x="143.8" y="200">5k1</text>
<text x="152.5" y="202.5">GND</text>
<text x="169.1" y="204">D6</text>
<text x="88.9" y="206.4">R14</text>
<text x="89.2" y="208.7">5k1</text>
<text x="165.9" y="206.3">ESD5302F</text>
<text x="236.4" y="209.6">U5</text>
<text x="97" y="215.3">LED</text>
<text x="97.2" y="213">D3</text>
<text x="124.9" y="214">D+</text>
<text x="133.6" y="210.1">R22</text>
<text x="141.1" y="210.1">DNP</text>
<text x="141.1" y="212.7">DNP</text>
<text x="179.1" y="212.7">GND</text>
<text x="216.8" y="210.3">+5V</text>
<text x="232.2" y="215.3">IN</text>
<text x="232.4" y="211.9">SY6280AAC</text>
<text x="239.1" y="215.3">OUT</text>
<text x="286.2" y="210.3">+5V_USBOTG</text>
<text x="92" y="221.7">GND</text>
<text x="124.9" y="216.6">D+</text>
<text x="221.1" y="218">C42</text>
<text x="221.1" y="220.3">47u</text>
<text x="238.9" y="217.8">ISET</text>
<text x="252" y="219.3">R36</text>
<text x="252" y="221.6">5k1</text>
<text x="259.6" y="218">R37</text>
<text x="259.6" y="220.3">2k2</text>
<text x="268" y="218">C43</text>
<text x="268.1" y="220.3">47u</text>
<text x="276.9" y="218">C45</text>
<text x="277" y="220.3">47u</text>
<text x="300.4" y="217.8">OTG</text>
<text x="300.7" y="220.1">J4</text>
<text x="309.1" y="220.4">R39</text>
<text x="111.1" y="227.6" transform="rotate(-90 111.1 227.6)">SHIELD</text>
<text x="118.7" y="227.6" transform="rotate(-90 118.7 227.6)">GND</text>
<text x="122.5" y="224.2">SBU1</text>
<text x="122.5" y="226.7">SBU2</text>
<text x="216.5" y="225.5">GND</text>
<text x="232.2" y="222.9">EN</text>
<text x="238.9" y="222.9">GND</text>
<text x="244.4" y="226.8">GNDGND</text>
<text x="263.5" y="225.5">GND</text>
<text x="272.4" y="225.5">GND</text>
<text x="309.2" y="222.7">5k1</text>
<text x="221" y="232">R35</text>
<text x="252.8" y="233.2">R38</text>
<text x="268" y="233.2">C44</text>
<text x="290.1" y="228.1">GND</text>
<text x="305.5" y="228.6">GND</text>
<text x="100.8" y="239.4">200k</text>
<text x="101.7" y="237">R21</text>
<text x="113.1" y="239.4">1n</text>
<text x="113.1" y="237">C13</text>
<text x="116.2" y="238.2">GND</text>
<text x="221.3" y="234.3">5k1</text>
<text x="224.1" y="239.5">GND</text>
<text x="253" y="235.5">3k9</text>
<text x="268.2" y="235.5">100n</text>
<text x="108.5" y="245.8">GND</text>
<text x="255.9" y="240.8">GND</text>
<text x="263.5" y="240.8">GND</text>
</g>
<g font-size="1.8" fill="#008400">
<text x="267.6" y="121.4">R34</text>
<text x="50.2" y="139.2">SW3</text>
<text x="133.6" y="212.7">R23</text>
</g>
<g font-size="1.8" fill="#0000c2">
<text x="177.9" y="154.4">GND 1V3</text>
<text x="182.9" y="152.2">3V3</text>
<text x="118.1" y="161.1">I2C Address: 0x34</text>
<text x="250.2" y="163.6">1V5</text>
<text x="111.8" y="186.5">USB Power in</text>
<text x="260.3" y="210.6">OTG</text>
</g>
<g font-size="1.6" fill="#008484">
<text x="345.5" y="125.1">GND21</text>
<text x="345.5" y="127.6">GND20</text>
<text x="345.5" y="130.1">GND19</text>
</g>
<g font-size="1.4" fill="#840000">
<text x="113.5" y="36.6">37</text>
<text x="138.9" y="36.6">38</text>
<text x="138.9" y="39.2">39</text>
<text x="113.5" y="44.2">34</text>
<text x="113.5" y="46.8">35</text>
<text x="138.9" y="46.8">42</text>
<text x="138.9" y="49.3">43</text>
<text x="113.5" y="54.4">32</text>
<text x="113.5" y="56.9">33</text>
<text x="138.9" y="54.4">45</text>
<text x="138.9" y="59.5">46</text>
<text x="113.5" y="64.6">31</text>
<text x="138.9" y="62">44</text>
<text x="113.5" y="69.6">49</text>
<text x="139.3" y="69.6">8</text>
<text x="113.9" y="74.7">3</text>
<text x="113.9" y="77.3">5</text>
<text x="138.9" y="72.2">10</text>
<text x="139.3" y="77.3">7</text>
<text x="139.3" y="74.7">9</text>
<text x="113.5" y="79.8">18</text>
<text x="113.5" y="82.3">19</text>
<text x="113.5" y="87.4">36</text>
<text x="138.9" y="84.9">15</text>
<text x="138.9" y="90">16</text>
<text x="138.9" y="87.4">17</text>
<text x="113.5" y="92.5">30</text>
<text x="138.9" y="92.5">14</text>
<text x="113.5" y="97.6">26</text>
<text x="138.9" y="100.1">13</text>
<text x="113.5" y="105.2">22</text>
<text x="113.5" y="102.7">23</text>
<text x="138.9" y="107.7">28</text>
<text x="113.5" y="110.3">24</text>
<text x="113.5" y="115.4">21</text>
<text x="138.9" y="115.4">12</text>
<text x="113.5" y="123">20</text>
<text x="138.9" y="123">41</text>
<text x="113.5" y="130.6">47</text>
<text x="138.9" y="130.6">40</text>
<text x="138.9" y="138.2">11</text>
<text x="113.9" y="145.8">4</text>
<text x="113.9" y="148.4">6</text>
<text x="138.9" y="145.8">25</text>
<text x="113.5" y="150.9">48</text>
<text x="113.9" y="156">1</text>
<text x="113.9" y="153.5">2</text>
<text x="138.9" y="153.5">27</text>
<text x="138.9" y="156">29</text>
<text x="246" y="171.2">1</text>
<text x="246" y="173.8">2</text>
<text x="246" y="168.7">4</text>
<text x="258.7" y="168.7">3</text>
<text x="258.7" y="173.8">5</text>
</g>
<g font-size="1.4" fill="#008484">
<text x="117.9" y="37.4">TS</text>
<text x="133.2" y="37.4">BAT</text>
<text x="133.2" y="39.9">BAT</text>
<text x="117.9" y="45">IPSOUT</text>
<text x="117.9" y="47.5">IPSOUT</text>
<text x="128.4" y="47.5">BATSENSE</text>
<text x="129.3" y="50.1">CHSENSE</text>
<text x="117.9" y="55.2">ACIN</text>
<text x="117.9" y="57.7">ACIN</text>
<text x="133.6" y="55.2">LX1</text>
<text x="117.9" y="65.3">VBUS</text>
<text x="131.3" y="60.2">PGND1</text>
<text x="133" y="62.8">VIN1</text>
<text x="117.9" y="70.4">Exposed_Pad(GND)</text>
<text x="133.6" y="70.4">LX2</text>
<text x="117.9" y="75.5">GPIO3</text>
<text x="131.3" y="72.9">DCDC2</text>
<text x="131.3" y="75.5">PGND2</text>
<text x="117.9" y="80.6">GPIO1</text>
<text x="117.9" y="83.1">GPIO0/LDO5</text>
<text x="117.9" y="78">GPIO2</text>
<text x="133" y="78">VIN2</text>
<text x="117.9" y="88.2">CHGLED</text>
<text x="131.3" y="88.2">DCDC3</text>
<text x="133.6" y="85.6">LX3</text>
<text x="117.9" y="93.3">BACKUP</text>
<text x="131.3" y="90.7">PGND3</text>
<text x="133" y="93.3">VIN3</text>
<text x="117.9" y="98.3">VINT</text>
<text x="130.2" y="100.9">LDO24IN</text>
<text x="117.9" y="106">AGND</text>
<text x="117.9" y="103.4">BIAS</text>
<text x="117.9" y="111">VREF</text>
<text x="132.4" y="108.5">LDO1</text>
<text x="117.9" y="116.1">APS</text>
<text x="132.4" y="116.1">LDO2</text>
<text x="117.9" y="123.7">EXTEN</text>
<text x="132.4" y="123.7">LDO3</text>
<text x="117.9" y="131.4">PWRON</text>
<text x="131" y="131.4">LDO3IN</text>
<text x="132.4" y="139">LDO4</text>
<text x="117.9" y="146.6">N_OE</text>
<text x="117.9" y="149.1">N_VBUSEN</text>
<text x="130.7" y="146.6">PWROK</text>
<text x="117.9" y="154.2">SCK</text>
<text x="117.9" y="151.7">IRQ/WAKEUP</text>
<text x="129.6" y="154.2">LDO1SET</text>
<text x="117.9" y="156.8">SDA</text>
<text x="130.6" y="156.8">DC3SET</text>
<text x="248.7" y="172">EN</text>
<text x="248.7" y="169.5">IN</text>
<text x="255" y="169.5">LX</text>
<text x="248.3" y="178.4">SY8089AAAC</text>
<text x="248.7" y="174.5">GND</text>
<text x="254.9" y="174.5">FB</text>
</g>
<text font-size=".9" fill="#008484" x="297.7" y="70.2">Port B,C,F,G</text>
<g font-size=".8" fill="#0000c2">
<text x="149.9" y="66.1">1.5A</text>
<text x="149.9" y="67.1">72mOhm</text>
<text x="149.9" y="81.3">1.5A</text>
<text x="149.9" y="82.4">72mOhm</text>
</g>
</g></defs>
<g fill="none" stroke="#840000" stroke-width=".18">
<path d="M10 10h400v277h-400zM12 12h396v273.1h-396zM60 10v2M110 10v2M160 10v2M210 10v2M260 10v2M310 10v2M360 10v2M73.7 36.9v1.2l-1.3-1.2 1.3-1.3v1.3h1.2M76.2 36.9h.8M80.5 36.9h.8"/>
<path d="M111.8 36.9h5M116.8 34.3h20.4v124.5h-20.4zM137.2 36.9h5M137.2 39.4h5M147.3 38.1v2.1M72.4 44.5l1.3 .7M72.4 44.5h2.5M72.4 54.6l1.3 .8M72.4 54.6h2.5M73.7 50.8v1.3l-1.3-1.3 1.3-1.2v1.2h1.2M73.7 43.7l-1.3 .8M73.7 53.9l-1.3 .7"/>
<path d="M76.2 45.8v2M76.2 48.8v2M76.2 54.6v7.7M85.1 45.8v2M85.1 48.8v2M91.4 55.9v2M91.4 59v2M100.3 55.9v2M100.3 59v2M111.8 44.5h5M111.8 54.6h5M111.8 57.2h5"/>
<path d="M111.8 47h5M137.2 59.7h6.3v1.3l1.3-1.3-1.3-1.2v1.2M137.2 54.6h5M137.2 47h5M137.2 49.6h5M147.3 41.2v3.3h-1.3l1.3 1.3 1.3-1.3h-1.3M167.6 51.3v3.3h-1.2l1.2 1.3 1.3-1.3h-1.3M167.6 48.3v2M10 60h2M72.4 64.8l1.3 .8M72.4 64.8h2.5M73.7 62.3v1.2l-1.3-1.2 1.3-1.3v1.3h1.2"/>
<path d="M73.7 72.4v1.3l-1.3-1.3 1.3-1.2v1.2h1.2M73.7 64l-1.3 .8M76.2 66.1v2M76.2 69.1v2.1M110.5 69.9v1.3l-1.3-1.3 1.3-1.3v1.3h6.3M111.8 64.8h5M111.8 77.5h5M111.8 75h5M137.2 75h6.3v1.2l1.3-1.2-1.3-1.3v1.3M137.2 69.9h5.5l.2-.3 .3-.2 .4 .1 .2 .4 .1-.3 .3-.2 .4 .1 .2 .4 .1-.3 .3-.2 .4 .1 .2 .4 .1-.3 .3-.2 .4 .1 .2 .4h.5M137.2 62.3h5M137.2 77.5h5"/>
<path d="M137.2 72.4h5M163.8 62.3v2M163.8 65.3v2M163.8 77.5v2M165.1 69.9v2M165.1 72.9v2.1M171.4 62.3v2M171.4 65.3v2M171.4 77.5v2M172.7 69.9v2M172.7 72.9v2.1M174 75h1.3v1.2l1.2-1.2-1.2-1.3v1.3"/>
<path d="M174 67.3h1.3v1.3l1.2-1.3-1.2-1.2v1.2M174 69.9h2.5M174 62.3h2.5M174 77.5h2.5M175.3 61.5l1.2 .8M175.3 76.7l1.2 .8M175.3 69.1l1.2 .8M176.5 62.3l-1.2 .7M176.5 77.5l-1.2 .8M176.5 69.9l-1.2 .7M260.3 76.2h2.6M260.3 76.2l1.3 .8"/>
<path d="M261.6 75.5l-1.3 .7M273 77.5v2M276.9 69.1v3.3h-1.3l1.3 1.3 1.2-1.3h-1.2M276.9 61v2.5M276.9 66.1v2M276.9 61l-.8 1.3M276.9 61l.7 1.3M281.9 77.5v2M290.8 78.8h5.1M290.8 68.6h5.1M290.8 76.2h5.1M290.8 71.2h5.1"/>
<path d="M295.9 66.1h55.9v66h-55.9zM303.1 69.6a.28 .28 0 0 0-.4 .3 .28 .28 0 0 0 .4 .2v-.2h-.1M306.1 61v5.1M308.6 61v5.1M311.1 61v5.1M313.7 61v5.1M316.2 61v5.1M318.8 61v5.1M321.3 61v5.1M323.8 61v5.1M326.4 61v5.1M328.9 61v5.1"/>
<path d="M331.5 61v5.1M334 61v5.1M336.5 61v5.1M339.1 61v5.1M341.6 61v5.1M344.2 61v1.3h-1.3l1.3 1.2 1.2-1.2h-1.2M351.8 78.8h5.1M351.8 68.6h5.1M351.8 76.2h5.1M351.8 71.2h5.1M351.8 73.7h5.1M408 60h2"/>
<path d="M72.4 82.6l1.3 .7M72.4 82.6h2.5M73.7 88.9v1.3l-1.3-1.3 1.3-1.2v1.2h1.2M73.7 81.8l-1.3 .8M76.2 83.9v2M76.2 86.9v2M111.8 82.6h5M111.8 92.7h5M111.8 87.7h5M111.8 80h5M111.8 97.8h5M137.2 85.1h5.5l.2-.3 .3-.2 .4 .1 .2 .4 .1-.3 .3-.2 .4 .1 .2 .4 .1-.3 .3-.2 .4 .1 .2 .4 .1-.3 .3-.2 .4 .1 .2 .4h.5"/>
<path d="M137.2 90.2h6.3v1.3l1.3-1.3-1.3-1.3v1.3M137.2 92.7h5M137.2 87.7h5M143.5 99.6l1.3 .8M163.8 80.6v2M165.1 85.1v2.1M165.1 88.2v2M171.4 80.6v2M172.7 85.1v2.1M172.7 88.2v2M172.7 92.7v2.1M172.7 95.8v2"/>
<path d="M174 97.8h1.3v1.3l1.2-1.3-1.2-1.2v1.2M174 90.2h1.3v1.3l1.2-1.3-1.2-1.3v1.3M174 82.6h1.3v1.3l1.2-1.3-1.2-1.3v1.3M174 85.1h2.5M174 92.7h2.5M175.3 92l1.2 .7M175.3 84.4l1.2 .7M176.5 92.7l-1.2 .8M176.5 85.1l-1.2 .8M251.5 88.9h2.5M251.5 88.9l1.2 .8M252.7 96.6v1.2l-1.2-1.2 1.2-1.3v1.3h1.3"/>
<path d="M252.7 88.2l-1.2 .7M261.6 83.9v1.2l-1.3-1.2 1.3-1.3v1.3h1.3M262.9 90.2v2M262.9 93.3v2M273 80.6v2M273 90.2v2M273 93.3v2M281.9 80.6v2M290.8 99.1h5.1M290.8 81.3h5.1M290.8 96.6h5.1M290.8 94h5.1"/>
<path d="M290.8 91.5h5.1M290.8 88.9h5.1M290.8 83.9h5.1M351.8 99.1h5.1M351.8 81.3h5.1M351.8 96.6h5.1M351.8 94h5.1M351.8 91.5h5.1M351.8 88.9h5.1M351.8 86.4h5.1M351.8 83.9h5.1M10 110h2"/>
<path d="M72.4 115.6l1.3 .8M72.4 115.6h2.5M73.7 110.5v1.3l-1.3-1.3 1.3-1.2v1.2h1.2M73.7 102.9v1.3l-1.3-1.3 1.3-1.3v1.3h1.2M73.7 114.8l-1.3 .8M76.2 116.9v2M76.2 119.9v2.1M76.2 110.5h2M76.2 102.9h.8M79.2 110.5h2.1M80.5 102.9h.8M110.5 105.4v1.3l-1.3-1.3 1.3-1.2v1.2h6.3"/>
<path d="M111.8 110.5h5M111.8 102.9h5M111.8 115.6h5M137.2 108h5M137.2 115.6h5M137.2 100.4h7.6M144.8 100.4l-1.3 .7M172.7 108v2M172.7 111v2.1M172.7 115.6v2M172.7 118.7v2M174 113.1h1.3v1.2l1.2-1.2-1.2-1.3v1.3"/>
<path d="M174 108h2.5M174 115.6h2.5M175.3 107.2l1.2 .8M175.3 114.8l1.2 .8M176.5 108l-1.2 .7M176.5 115.6l-1.2 .8M246.4 111.8v1.3l-1.3-1.3 1.3-1.3v1.3h1.2M246.4 104.2h1.2M254 105.4v2.1M254 108.5v2M262.9 105.4v2.1M262.9 108.5v2"/>
<path d="M273 105.4v2.1M273 108.5v2M281.9 105.4v2.1M281.9 108.5v2M290.8 104.2h5.1M290.8 116.9h5.1M290.8 114.3h5.1M290.8 111.8h5.1M290.8 109.3h5.1M290.8 106.7h5.1M351.8 104.2h5.1M351.8 101.6h5.1"/>
<path d="M351.8 119.4h5.1M351.8 116.9h5.1M351.8 114.3h5.1M351.8 111.8h5.1M351.8 109.3h5.1M351.8 106.7h5.1M408 110h2M49.5 139.7v1.3l-1.2-1.3 1.2-1.2v1.2h1.3M52.1 139.7h2.5M54.6 138.5h5.1M57.1 136.7v1.8M59.7 139.7h2.5"/>
<path d="M73.7 122v1.2l-1.3-1.2 1.3-1.3v1.3h1.2M73.7 130.8v1.3l-1.3-1.3 1.3-1.2v1.2h1.2M78.7 139.7h.8M78.7 130.8h2.1M81.8 130.8h2M83.1 139.7h.7M99.1 139.7h2.5M101.6 139.2h1.5v1h-1.5zM103.1 139.7h4.1M103.6 137.5h1v1.5h-1zM104.1 139v.7M106.7 133.4l1.2 .7"/>
<path d="M106.7 133.4h2.5M107.9 132.6l-1.2 .8M109.2 136.7h-5.1v.8M109.2 134.7v2.5l-1.9 1.9M111.8 130.8h5M111.8 123.2h5M137.2 130.8h5M137.2 138.5h5M137.2 123.2h5M172.7 123.2v2.1M172.7 126.3v2M172.7 130.8v2.1"/>
<path d="M172.7 133.9v2M172.7 138.5v2M174 120.7h1.3v1.3l1.2-1.3-1.2-1.3v1.3M174 128.3h1.3v1.3l1.2-1.3-1.2-1.3v1.3M174 135.9h1.3v1.3l1.2-1.3-1.2-1.2v1.2M174 130.8h2.5M174 138.5h2.5M174 123.2h2.5M175.3 130.1l1.2 .7M175.3 137.7l1.2 .8M175.3 122.5l1.2 .7M176.5 130.8l-1.2 .8"/>
<path d="M176.5 138.5l-1.2 .7M176.5 123.2l-1.2 .8M266.7 122v1.2l-1.3-1.2 1.3-1.3v1.3h1.3M274.8 122h.8M290.8 130.8v1.3h-1.2l1.2 1.3 1.3-1.3h-1.3M290.8 122h5.1M290.8 127h5.1M290.8 129.6h5.1M303.5 138.5v1.2h-1.2l1.2 1.3 1.3-1.3h-1.3M303.5 132.1v5.1M306.1 132.1v5.1M308.6 132.1v5.1"/>
<path d="M311.1 132.1v5.1M313.7 132.1v5.1M316.2 132.1v5.1M318.8 132.1v5.1M321.3 132.1v5.1M323.8 132.1v5.1M326.4 132.1v5.1M328.9 132.1v5.1M331.5 132.1v5.1M334 132.1v5.1M336.5 132.1v5.1M339.1 132.1v5.1"/>
<path d="M341.6 132.1v5.1M344.2 132.1v5.1M351.8 122h5.1M351.8 127h5.1M351.8 124.5h5.1M351.8 129.6h5.1M356.9 130.8v1.3h-1.3l1.3 1.3 1.2-1.3h-1.2M72.4 151.2h2.5M72.4 151.2l1.3 .7M73.7 146.1v1.3l-1.3-1.3 1.3-1.3v1.3h1.2M73.7 150.4l-1.3 .8M83.1 146.1h.7"/>
<path d="M83.1 151.2h.7M107.3 140.4l1.9 1.9v2.5M111.8 146.1h5M111.8 151.2h5M111.8 153.7h5M111.8 156.2h5M111.8 148.6h5M116.8 153.2l1.1 .5-1.1 .5M137.2 146.1h5M137.2 153.7h5M137.2 156.2h7.6M143.5 155.5l1.3 .7"/>
<path d="M144.8 156.2l-1.3 .8M154.9 146.1h.8M159.3 146.1h.7M168.1 151.2h.8M168.1 153.7h.8M172.7 141.5v2M174 143.5h1.3v1.3l1.2-1.3-1.2-1.2v1.2M174 153.7h1.3v1.3l1.2-1.3-1.2-1.3v1.3M174 146.1h2.5M175.3 145.3l1.2 .8M176.5 146.1l-1.2 .7M10 160h2"/>
<path d="M232.4 173.3v3.3h1.3l-1.3 1.2-1.3-1.2h1.3M232.4 165.1v2.6M232.4 170.2v2M232.4 165.1l-.8 1.3M232.4 165.1l.8 1.3M242.6 171.5l1.2 .7M242.6 171.5h5M243.8 174v-1.2l-1.2 1.2 1.2 1.3v-1.3h3.8M243.8 170.7l-1.2 .8M245.1 168.9h2.5M247.6 166.4h10.2v10.2h-10.2zM257.8 168.9h2.5"/>
<path d="M257.8 174h2.5M261.6 168.9h.5l.2-.3 .2-.2 .5 .2 .1 .3 .2-.3 .3-.2 .4 .2 .2 .3 .1-.3 .3-.2 .4 .2 .2 .3 .1-.3 .3-.2 .4 .2 .2 .3h.5M268 170.2v.8M268 174.5v.8M268 177.8v.8M275.6 173.3v3.3h1.3l-1.3 1.2-1.3-1.2h1.3M275.6 166.4v1.3M275.6 170.2v2M408 160h2M127.3 195.4h1v.5h-1zM128.3 195.6h7.6M134.6 194.9l1.3 .7"/>
<path d="M135.9 195.6l-1.3 .8M268 187.2v2.1h1.2l-1.2 1.2-1.3-1.2h1.3M268 182.2v1.5M10 210h2M94 208.8v9.7h-1.3l1.3 1.2 1.2-1.2h-1.2M94 202v3.3M94 202l-.8 1.2M94 202l.7 1.2M94.7 216.4l1.6 1.6v-.8v.8h-.8M94.7 215.2l1.6 1.5v-.8v.8h-.8M127.3 215.7h1v.5h-1zM127.3 213.1h1v.6h-1z"/>
<path d="M127.3 210.6h1v.5h-1zM127.3 208.1h1v.5h-1zM127.3 203h1v.5h-1zM127.3 200.4h1v.6h-1zM128.3 203.2h5M128.3 200.7h5M128.3 213.4h5M128.3 208.3h5M128.3 215.9h5M128.3 210.9h5M135.9 213.4h.8M138.4 203.2h.8"/>
<path d="M140.2 213.4h.8M140.2 210.9h.8M142.7 203.2h.8M142.7 200.7h.8M148.6 202h1.3v-1.3l1.2 1.3-1.2 1.2v-1.2M165.1 214.7h3.8M165.1 209.6h3.8M168.9 213.9v1.5h.3M168.9 209.6h2.5v5.1h-2.5M168.9 214.7l1.3-.7v1.3zM168.9 208.8v1.5h.3M168.9 209.6l1.3-.6v1.2z"/>
<path d="M171.4 212.1h5.1v-1.2l1.3 1.2-1.3 1.3v-1.3M218.4 219v3.3h1.3l-1.3 1.3-1.2-1.3h1.2M218.4 210.9l-.7 1.2M218.4 210.9v2.5M218.4 215.9v2.1M218.4 210.9l.8 1.2M228.6 214.7h2.5M231.1 213.4h12.7v10.2h-12.7zM243.8 217.2h2.6M243.8 214.7h2.6M250.2 217.2v.8M257.8 215.9v.8"/>
<path d="M265.4 219v3.3h1.3l-1.3 1.3-1.2-1.3h1.2M265.4 215.9v2.1M274.3 219v3.3h1.3l-1.3 1.3-1.3-1.3h1.3M274.3 215.9v2.1M292.1 210.9l-.8 1.2M292.1 210.9v2.5M292.1 210.9l.8 1.2M293.4 219.7h3.8M293.4 217.2h3.8M293.4 214.7h3.8M297.2 214.5h1.2v.3h-1.2zM297.2 217.1h1.2v.2h-1.2z"/>
<path d="M297.2 219.6h1.2v.3h-1.2zM307.3 218.5v.7M408 210h2M106.7 235v.7M106.7 239.3v.8M110.5 228.6v5.1M110.5 235v2M110.5 238v2.1M117.9 227.6h.5v1h-.5zM118.1 228.6v6.4h-1.3l1.3 1.3 1.3-1.3h-1.3M127.3 225.8h1v.6h-1zM127.3 223.3h1v.5h-1z"/>
<path d="M128.3 223.6h5M128.3 226.1h5M226.1 234.2v2.1h1.2l-1.2 1.2-1.3-1.2h1.3M226.1 229.9v.8M228.6 222.3h2.5M243.8 222.3h2.6v1.3h1.2l-1.2 1.2-1.3-1.2h1.3M250.2 221.5v2.1h1.3l-1.3 1.2-1.3-1.2h1.3M257.8 235.5v2h1.3l-1.3 1.3-1.3-1.3h1.3M257.8 220.3v.7M257.8 231.2v.7M265.4 234.2v3.3h1.3l-1.3 1.3-1.2-1.3h1.2M265.4 231.2v2"/>
<path d="M292.1 223.6v1.2h1.3l-1.3 1.3-1.3-1.3h1.3M293.4 222.3h3.8M297.2 222.2h1.2v.2h-1.2zM307.3 222.8v2h1.3l-1.3 1.3-1.2-1.3h1.2M110.5 241.3v1.3h-1.3l1.3 1.3 1.3-1.3h-1.3M300 253h108v32.1h-108zM10 260h2M300 278.5h108M300 274.5h108M300 268.5h108M309 279.3h1l-.5 .6 .4 .1v.7l-.2 .1-.7-.1M315.4 270.2l.7-.1v-.3l-.5-.1-.2 .2 .1 .7h.6"/>
<path d="M316.5 272.5l-.4-.1-.3 .3 .1 .6 .2 .1 .4-.1M316.8 269.7v1M317.2 272.5a.37 .37 0 0 1 .6 .1v.8M317.2 269.7l-.4 .1v.2M317.2 271.9v1.5M318.7 269.1l-1.2 2M320 278.5v3M384 278.5v6.6M408 260h2M60 285.1v1.9M110 285.1v1.9M160 285.1v1.9"/>
<path d="M210 285.1v1.9M260 285.1v1.9M300 281.5h108M310 285.1v1.9M338.4 283h1.1M340.2 282.3l.5-.2 .3 .4-.9 1.1h.9M341.7 282.7l.4-.1 .3 .3-.2 .6h-.5M341.7 282.1v1.5M343 282.6l.1 .9 .3 .1 .3-.1M343.7 282.6v1M344.4 282.1v.2M344.4 282.6v1"/>
<path d="M345.1 282.1v1.3l.2 .2M346.5 282.7l-.4-.1-.3 .3 .1 .6 .2 .1 .4-.1M346.5 282.1v1.5M347.1 282.3l.6-.2 .3 .4-.9 1.1h.9M360 285.1v1.9M392.8 282l-1.3 2M394 282.1h-.7l-.1 .7 .3-.1h.5l.1 .3-.1 .5-.2 .1-.6-.1"/>
<circle cx="245.7" cy="104.2" r=".63"/>
<circle cx="55.1" cy="139.7" r=".51"/>
<circle cx="59.2" cy="139.7" r=".51"/>
<circle cx="275.6" cy="165.8" r=".63"/>
</g>
<g fill="none" stroke="#840000" stroke-width=".3">
<path d="M74.7 47.8h3M83.6 47.8h3M89.9 57.9h3.1M98.8 57.9h3.1M145.8 40.2h3M166.1 50.3h3.1M74.7 68.1h3M162.3 79.5h3.1M162.3 64.3h3.1M163.6 71.9h3M169.9 79.5h3.1M169.9 64.3h3.1"/>
<path d="M171.2 71.9h3M271.5 79.5h3.1M275.3 68.1h3.1M280.4 79.5h3.1M74.7 85.9h3M163.6 87.2h3M171.2 94.8h3M171.2 87.2h3M261.4 92.2h3M271.5 92.2h3.1M74.7 118.9h3M78.2 109v3.1"/>
<path d="M171.2 117.6h3M171.2 110h3M252.5 107.5h3M261.4 107.5h3M271.5 107.5h3.1M280.4 107.5h3.1M81.8 129.3v3.1M171.2 125.3h3M171.2 132.9h3M171.2 140.5h3M230.9 172.2h3M274.1 172.2h3"/>
<path d="M216.9 218h3.1M263.9 218h3.1M272.8 218h3M109 237h3M263.9 233.2h3.1M394.5 279.5l.2-.2a.81 .81 0 0 1 .6 .6 .81 .81 0 0 1-.3 .8l-.1 .1a.79 .79 0 0 1-.4-1.3z"/>
</g>
<path d="M332.7 275.2l.4 2 .9-2M334.5 275.4l.3-.2h.5l.3 .2v.4l-.1 .3-1.3 1.1h1.3" fill="none" stroke="#840000" stroke-width=".41"/>
<g fill="none" stroke="#840000" stroke-width=".33">
<path d="M74.7 48.8h3M83.6 48.8h3M89.9 59h3.1M98.8 59h3.1M145.8 41.2h3M166.1 51.3h3.1M74.7 69.1h3M162.3 65.3h3.1M163.6 72.9h3M169.9 65.3h3.1M171.2 72.9h3M275.3 69.1h3.1"/>
<path d="M74.7 86.9h3M162.3 80.6h3.1M163.6 88.2h3M169.9 80.6h3.1M171.2 95.8h3M171.2 88.2h3M261.4 93.3h3M271.5 80.6h3.1M271.5 93.3h3.1M280.4 80.6h3.1M74.7 119.9h3M79.2 109v3.1"/>
<path d="M171.2 118.7h3M171.2 111h3M252.5 108.5h3M261.4 108.5h3M271.5 108.5h3.1M280.4 108.5h3.1M80.8 129.3v3.1M171.2 126.3h3M171.2 133.9h3M171.2 141.5h3M230.9 173.3h3M274.1 173.3h3"/>
<path d="M216.9 219h3.1M263.9 219h3.1M272.8 219h3M109 238h3M263.9 234.2h3.1"/>
</g>
<g fill="none" stroke="#840000" stroke-width=".2">
<path d="M77 36.1h3.5v1.5h-3.5zM74.9 55.9h2.6l-1.3 2.6zM74.9 57.9v.6h2.6v.5M76.2 58.5l1.3 2.5h-2.6zM77 102.1h3.5v1.6h-3.5zM79.5 139h3.6v1.5h-3.6zM271.3 121.2h3.5v1.5h-3.5zM79.5 150.4h3.6v1.5h-3.6zM79.5 145.3h3.6v1.5h-3.6zM155.7 145.3h3.6v1.5h-3.6zM164.6 150.4h3.5v1.5h-3.5zM164.6 152.9h3.5v1.6h-3.5z"/>
<path d="M267.2 178.6h1.5v3.6h-1.5zM267.2 171h1.5v3.5h-1.5zM139.2 199.9h3.5v1.6h-3.5zM267.2 183.7h1.5v3.5h-1.5zM92.7 212.1h2.5l-1.2 2.6zM92.7 214.7h2.5M93.2 205.3h1.5v3.5h-1.5zM136.7 210.1h3.5v1.5h-3.5zM136.7 212.6h3.5v1.6h-3.5zM139.2 202.5h3.5v1.5h-3.5zM249.4 218h1.6v3.5h-1.6zM257 216.7h1.6v3.6h-1.6z"/>
<path d="M306.6 219.2h1.5v3.6h-1.5zM105.9 235.7h1.5v3.6h-1.5zM225.3 230.7h1.5v3.5h-1.5zM257 231.9h1.6v3.6h-1.6z"/>
</g>
<g fill="#ffffc2" stroke="#ffffc2" stroke-width=".18">
<path d="M107.9 193.1h20.4v35.5h-20.4z"/>
<path d="M297.2 213.4h2.5v10.2h-2.5z"/>
<path d="M231.1 213.4h12.7v10.2h-12.7z"/>
<path d="M295.9 66.1h55.9v66h-55.9z"/>
<path d="M167.6 207.7h5.1v8.9h-5.1z"/>
<path d="M247.6 166.4h10.2v10.2h-10.2z"/>
<path d="M116.8 34.3h20.4v124.5h-20.4z"/>
</g>
<g fill="none" stroke="#840000" stroke-width=".25">
<path d="M166.5 40.2h2.3v7.5l-1.2 .6-1.1-.6zM106.6 96.7h4.5l.7 1.1-.7 1.1h-4.5zM104.7 122.1h6.4l.7 1.1-.7 1.1h-6.4zM52.1 142.4h9.5l.6 1.1-.6 1.2h-9.5zM74 152.6h9.2l.6 1.1-.6 1.1h-9.2zM74.1 155.1h9.1l.6 1.1-.6 1.2h-9.1zM102.1 147.5h9l.7 1.1-.7 1.1h-9zM145.4 142.4h7.5v2.3h-7.5l-.6-1.2zM174.6 150h4.6v2.3h-4.6l-.6-1.1zM107.9 193.1h20.4v35.5h-20.4zM110.5 214.7a.63 .63 0 0 0 .6 .6 .63 .63 0 0 0 .7-.6M110.5 207a.63 .63 0 0 1 .6-.6 .63 .63 0 0 1 .7 .6"/>
<path d="M145.4 212.3h8.9v2.2h-8.9l-.6-1.1zM145.4 209.7h9v2.3h-9l-.6-1.1zM155.5 208.5h9l.6 1.1-.6 1.1h-9zM155.6 213.5h8.9l.6 1.2-.6 1.1h-8.9zM167.6 207.7h5.1v8.9h-5.1zM283.8 216.1h8.9l.7 1.1-.7 1.1h-8.9zM283.9 218.6h8.8l.7 1.1-.7 1.2h-8.8zM297.2 213.4h2.5v10.2h-2.5zM306.2 210.6h2.3v7.2l-1.2 .7-1.1-.7zM215.2 227.5h9l.6 1.1-.6 1.2h-9zM267.3 228.8h13.7v2.2h-13.7l-.6-1.1z"/>
<circle cx="107.9" cy="139.7" r="2.82"/>
</g>
<path d="M107.3 138.2v3.1M109.7 205.8a1.9 1.9 0 0 1 2.1-.6 1.9 1.9 0 0 1 1.2 1.8v7.7a1.9 1.9 0 0 1-1.9 1.9 1.9 1.9 0 0 1-1.9-1.9v-7.8l.1-.5zM115.6 210.3v1.3l2.5 2.6M118.1 206.5v10.2M120.6 209.1v1.2l-2.5 2.6" fill="none" stroke="#840000" stroke-width=".51"/>
<g fill="#840000" stroke="#840000" stroke-width=".25">
<path d="M110.5 214.7h1.3a.63 .63 0 0 1-.7 .6 .63 .63 0 0 1-.6-.6z"/>
<path d="M110.7 206.6a.63 .63 0 0 1 .7-.2 .63 .63 0 0 1 .4 .6h-1.3z"/>
<path d="M110.5 207h1.3v7.7h-1.3z"/>
<path d="M120 207.8h1.3v1.3h-1.3z"/>
<path d="M118.1 204l1.3 2.5h-2.6z"/>
<circle cx="115.6" cy="209.7" r=".63"/>
</g>
<g fill="#840000" stroke="#840000" stroke-width=".18">
<path d="M108.5 137.5l.5 .5-1.1 .5z"/>
<circle cx="118.1" cy="216.7" r="1.27"/>
<circle cx="104.1" cy="139.7" r=".25"/>
<circle cx="171.4" cy="212.1" r=".25"/>
</g>
<g fill="none" stroke="#008484" stroke-width=".18">
<path d="M118.8 33.1l.4-1.3 .4 1.3M118.9 32.7h.6M134.6 31.6a1.47 1.47 0 0 1 0 1.9M311.8 59.3l.5-1.2 .4 1.2M312 59h.5M334.4 58l-.3 .9h.8M334.7 58.5v.8M335.3 57.9a1.47 1.47 0 0 1 0 1.9M130.7 69.3a.51 .51 0 0 1 .6 .5 .51 .51 0 0 1-.6 .5zM131.6 69.2a1.13 1.13 0 0 1 0 1.5M127.2 82h-.5l-.1 .5h.5l.1 .4-.2 .1-.4-.1M126.8 151.1h.5l.1-.4-.6-.1v1"/>
<path d="M124.6 207.6a.64 .64 0 0 1 .8 .6 .64 .64 0 0 1-.8 .7zM124.6 210.1a.64 .64 0 0 1 .8 .7 .64 .64 0 0 1-.8 .6zM125.9 208.4h1M125.9 210.9h1"/>
</g>
<g fill="none" stroke="#008400" stroke-width=".18">
<path d="M74.9 36.9h1.3M81.3 36.9h30.5M147.3 38.1v-1.2h-5.1v10.1M74.9 44.5h36.9M74.9 54.6h36.9M74.9 50.8h10.2M76.2 44.5v1.3M85.1 44.5v1.3M91.4 54.6v1.3M100.3 54.6v1.3M110.5 44.5v2.5h1.3M110.5 54.6v2.6h1.3"/>
<path d="M74.9 64.8h36.9M76.2 64.8v1.3M76.2 71.2v1.2h-1.3M91.4 61v1.3M100.3 61v1.3h-25.4M142.2 62.3h31.8M142.2 77.5h31.8M147.3 69.9h26.7M148.6 69.9v2.5h-6.4M163.8 67.3h10.2M165.1 75h8.9M262.9 76.2h27.9"/>
<path d="M273 76.2v1.3M276.9 64.8h8.8v6.4h5.1M276.9 63.5v2.6M281.9 76.2v1.3M285.7 76.2v7.7h5.1M285.7 78.8h5.1M285.7 68.6h5.1M306.1 61h38.1M356.9 68.6v62.2M74.9 82.6h36.9M74.9 88.9h1.3M76.2 82.6v1.3"/>
<path d="M142.2 92.7h31.8M147.3 85.1h26.7M148.6 85.1v2.6h-6.4M163.8 82.6h10.2M165.1 90.2h8.9M172.7 97.8h1.3M254 88.9h36.8M262.9 88.9v1.3M262.9 95.3v1.3M273 82.6v1.3M273 88.9v1.3M273 95.3v1.3"/>
<path d="M281.9 82.6v1.3h-19M281.9 88.9v1.3M281.9 95.3v1.3h-27.9M285.7 88.9v10.2h5.1M285.7 96.6h5.1M285.7 81.3h5.1M285.7 91.5h5.1M285.7 94h5.1M74.9 115.6h36.9M74.9 102.9h1.3M74.9 110.5h1.3M76.2 115.6v1.3"/>
<path d="M81.3 102.9h30.5M81.3 110.5h30.5M142.2 108h31.8M142.2 115.6h31.8M172.7 113.1h1.3M247.6 104.2h43.2M254 104.2v1.2M254 110.5v1.3M262.9 104.2v1.2M262.9 110.5v1.3M273 104.2v1.2M273 110.5v1.3"/>
<path d="M281.9 104.2v1.2M281.9 110.5v1.3h-34.3M285.7 104.2v12.7h5.1M285.7 111.8h5.1M285.7 109.3h5.1M285.7 114.3h5.1M285.7 106.7h5.1M62.2 139.7h16.5M64.8 139.7v3.8h-2.6M74.9 130.8h3.8M74.9 122h1.3M83.8 130.8h28"/>
<path d="M83.8 139.7h15.3M109.2 133.4v1.3M142.2 130.8h31.8M142.2 123.2h31.8M142.2 138.5h31.8M172.7 135.9h1.3M172.7 128.3h1.3M172.7 120.7h1.3M275.6 122h15.2M290.8 127v3.8M344.2 137.2h-40.7v1.3M74.9 146.1h3.8"/>
<path d="M74.9 151.2h3.8M83.8 146.1h28M83.8 151.2h28M83.8 153.7h28M83.8 156.2h28M109.2 144.8v1.3M142.2 146.1h12.7M142.2 153.7h21.6M144.8 143.5h-1.3v2.6M160 146.1h14M163.8 151.2h-5.1v2.5M168.9 151.2h5.1"/>
<path d="M168.9 153.7h5.1M172.7 143.5h1.3M232.4 167.7v2.5M232.4 168.9h12.7M260.3 174h3.9v2.6h3.8M260.3 168.9h1.3M266.7 168.9h8.9M268 168.9v1.3M268 175.3v2.5M275.6 167.7v2.5M133.3 203.2h5.1M133.3 200.7h5.1"/>
<path d="M133.3 208.3v2.6M135.9 213.4h-2.6v2.5M141 213.4h3.8M141 210.9h3.8M143.5 200.7h5.1v2.5h-5.1M218.4 213.4v2.5M218.4 214.7h10.2M246.4 214.7h47M246.4 217.2h3.8M257.8 214.7v1.2M265.4 214.7v1.2M274.3 214.7v1.2"/>
<path d="M292.1 213.4v1.3M110.5 233.7v1.3h-3.8M224.8 228.6h1.3M228.6 222.3h-2.5v7.6M257.8 229.9h8.9M257.8 221v10.2M265.4 229.9v1.3M293.4 222.3h-1.3v1.3M106.7 240.1h3.8v1.2"/>
</g>
<path d="M153.5 66.8l.2-.1v.4M153.5 82h.2v.3M133.5 159.7h.8l-.4 .5 .4 .1v.6l-.2 .1-.6-.1M135.1 159.7l-.3 .9h.8M135.4 160.2v.8M123.5 185.1v.2M123.5 185.6v.8M124.1 185.7l.2-.1h.3v.8M124.1 185.6v.8" fill="none" stroke="#0000c2" stroke-width=".18"/>
<g fill="#008400" stroke="#008400" stroke-width=".25">
<circle cx="285.7" cy="68.6" r=".51"/>
<circle cx="172.7" cy="90.2" r=".51"/>
<circle cx="285.7" cy="111.8" r=".51"/>
<circle cx="148.6" cy="202" r=".51"/>
<circle cx="171.5" cy="67.3" r=".51"/>
<circle cx="285.7" cy="109.3" r=".51"/>
<circle cx="165.1" cy="85.1" r=".51"/>
<circle cx="262.9" cy="96.6" r=".51"/>
<circle cx="262.9" cy="111.8" r=".51"/>
<circle cx="142.2" cy="36.9" r=".51"/>
<circle cx="273" cy="96.6" r=".51"/>
<circle cx="158.8" cy="153.7" r=".51"/>
<circle cx="285.7" cy="106.7" r=".51"/>
<circle cx="285.7" cy="81.3" r=".51"/>
<circle cx="281.9" cy="104.2" r=".51"/>
<circle cx="285.7" cy="96.6" r=".51"/>
<circle cx="285.7" cy="94" r=".51"/>
<circle cx="285.7" cy="91.5" r=".51"/>
<circle cx="273" cy="104.2" r=".51"/>
<circle cx="285.7" cy="88.9" r=".51"/>
<circle cx="265.4" cy="229.9" r=".51"/>
<circle cx="274.3" cy="214.7" r=".51"/>
<circle cx="285.7" cy="104.2" r=".51"/>
<circle cx="292.1" cy="214.7" r=".51"/>
<circle cx="133.4" cy="210.9" r=".51"/>
<circle cx="133.4" cy="213.4" r=".51"/>
<circle cx="285.7" cy="76.2" r=".51"/>
<circle cx="265.4" cy="214.7" r=".51"/>
<circle cx="262.9" cy="104.2" r=".51"/>
<circle cx="64.8" cy="139.7" r=".51"/>
<circle cx="172.7" cy="75" r=".51"/>
<circle cx="285.7" cy="114.3" r=".51"/>
<circle cx="273" cy="111.8" r=".51"/>
<circle cx="285.7" cy="78.8" r=".51"/>
<circle cx="165.1" cy="69.9" r=".51"/>
<circle cx="254" cy="104.2" r=".51"/>
<circle cx="142.2" cy="39.4" r=".51"/>
<circle cx="254" cy="111.8" r=".51"/>
<circle cx="356.9" cy="127" r=".51"/>
<circle cx="356.9" cy="96.6" r=".51"/>
<circle cx="356.9" cy="99.1" r=".51"/>
<circle cx="356.9" cy="101.6" r=".51"/>
<circle cx="356.9" cy="104.2" r=".51"/>
<circle cx="356.9" cy="106.7" r=".51"/>
<circle cx="143.5" cy="146.1" r=".51"/>
<circle cx="356.9" cy="109.3" r=".51"/>
<circle cx="356.9" cy="111.8" r=".51"/>
<circle cx="356.9" cy="114.3" r=".51"/>
<circle cx="356.9" cy="116.9" r=".51"/>
<circle cx="356.9" cy="119.4" r=".51"/>
<circle cx="356.9" cy="122" r=".51"/>
<circle cx="356.9" cy="124.5" r=".51"/>
<circle cx="356.9" cy="94" r=".51"/>
<circle cx="341.6" cy="137.2" r=".51"/>
<circle cx="303.5" cy="137.2" r=".51"/>
<circle cx="306.1" cy="137.2" r=".51"/>
<circle cx="110.5" cy="44.5" r=".51"/>
<circle cx="308.6" cy="137.2" r=".51"/>
<circle cx="311.1" cy="137.2" r=".51"/>
<circle cx="76.2" cy="50.8" r=".51"/>
<circle cx="313.7" cy="137.2" r=".51"/>
<circle cx="316.2" cy="137.2" r=".51"/>
<circle cx="76.2" cy="44.5" r=".51"/>
<circle cx="318.8" cy="137.2" r=".51"/>
<circle cx="321.3" cy="137.2" r=".51"/>
<circle cx="85.1" cy="44.5" r=".51"/>
<circle cx="268" cy="168.9" r=".51"/>
<circle cx="308.6" cy="61" r=".51"/>
<circle cx="313.7" cy="61" r=".51"/>
<circle cx="316.2" cy="61" r=".51"/>
<circle cx="318.8" cy="61" r=".51"/>
<circle cx="321.3" cy="61" r=".51"/>
<circle cx="323.8" cy="61" r=".51"/>
<circle cx="326.4" cy="61" r=".51"/>
<circle cx="328.9" cy="61" r=".51"/>
<circle cx="331.5" cy="61" r=".51"/>
<circle cx="334" cy="61" r=".51"/>
<circle cx="336.5" cy="61" r=".51"/>
<circle cx="275.6" cy="168.9" r=".51"/>
<circle cx="339.1" cy="61" r=".51"/>
<circle cx="323.8" cy="137.2" r=".51"/>
<circle cx="341.6" cy="61" r=".51"/>
<circle cx="356.9" cy="71.2" r=".51"/>
<circle cx="356.9" cy="129.6" r=".51"/>
<circle cx="356.9" cy="73.7" r=".51"/>
<circle cx="356.9" cy="76.2" r=".51"/>
<circle cx="232.4" cy="168.9" r=".51"/>
<circle cx="356.9" cy="78.8" r=".51"/>
<circle cx="356.9" cy="81.3" r=".51"/>
<circle cx="356.9" cy="83.9" r=".51"/>
<circle cx="268" cy="176.6" r=".51"/>
<circle cx="356.9" cy="86.4" r=".51"/>
<circle cx="356.9" cy="88.9" r=".51"/>
<circle cx="356.9" cy="91.5" r=".51"/>
<circle cx="172.7" cy="115.6" r=".51"/>
<circle cx="257.8" cy="214.7" r=".51"/>
<circle cx="163.8" cy="62.3" r=".51"/>
<circle cx="171.5" cy="62.3" r=".51"/>
<circle cx="311.1" cy="61" r=".51"/>
<circle cx="172.7" cy="69.9" r=".51"/>
<circle cx="171.5" cy="77.5" r=".51"/>
<circle cx="171.5" cy="82.6" r=".51"/>
<circle cx="172.7" cy="85.1" r=".51"/>
<circle cx="172.7" cy="92.7" r=".51"/>
<circle cx="148.6" cy="85.1" r=".51"/>
<circle cx="148.6" cy="69.9" r=".51"/>
<circle cx="172.7" cy="123.2" r=".51"/>
<circle cx="326.4" cy="137.2" r=".51"/>
<circle cx="172.7" cy="108" r=".51"/>
<circle cx="163.8" cy="77.5" r=".51"/>
<circle cx="172.7" cy="138.5" r=".51"/>
<circle cx="172.7" cy="130.8" r=".51"/>
<circle cx="276.9" cy="64.8" r=".51"/>
<circle cx="281.9" cy="76.2" r=".51"/>
<circle cx="273" cy="76.2" r=".51"/>
<circle cx="273" cy="83.9" r=".51"/>
<circle cx="281.9" cy="88.9" r=".51"/>
<circle cx="273" cy="88.9" r=".51"/>
<circle cx="110.5" cy="235" r=".51"/>
<circle cx="110.5" cy="240.1" r=".51"/>
<circle cx="331.5" cy="137.2" r=".51"/>
<circle cx="336.5" cy="137.2" r=".51"/>
<circle cx="339.1" cy="137.2" r=".51"/>
<circle cx="290.8" cy="129.6" r=".51"/>
<circle cx="109.2" cy="146.1" r=".51"/>
<circle cx="76.2" cy="115.6" r=".51"/>
<circle cx="218.4" cy="214.7" r=".51"/>
<circle cx="334" cy="137.2" r=".51"/>
<circle cx="76.2" cy="82.6" r=".51"/>
<circle cx="110.5" cy="54.6" r=".51"/>
<circle cx="76.2" cy="64.8" r=".51"/>
<circle cx="226.1" cy="228.6" r=".51"/>
<circle cx="76.2" cy="62.3" r=".51"/>
<circle cx="76.2" cy="54.6" r=".51"/>
<circle cx="91.4" cy="62.3" r=".51"/>
<circle cx="257.8" cy="229.9" r=".51"/>
<circle cx="91.4" cy="54.6" r=".51"/>
<circle cx="100.3" cy="54.6" r=".51"/>
<circle cx="328.9" cy="137.2" r=".51"/>
<circle cx="262.9" cy="88.9" r=".51"/>
</g>
<g fill="none" stroke="#000084" stroke-width=".18">
<path d="M141.6 49l1.2 1.2M141.6 54l1.2 1.3M142.8 49l-1.2 1.2M142.8 54l-1.2 1.3M111.2 76.9l1.2 1.2M111.2 74.4l1.2 1.2M111.2 79.4l1.2 1.3M112.4 76.9l-1.2 1.2M112.4 74.4l-1.2 1.2M112.4 79.4l-1.2 1.3M111.2 87.1l1.2 1.2M111.2 92.1l1.2 1.3"/>
<path d="M112.4 87.1l-1.2 1.2M112.4 92.1l-1.2 1.3M132.7 222.9l1.3 1.3M132.7 225.5l1.3 1.2M134 222.9l-1.3 1.3M134 225.5l-1.3 1.2"/>
</g>
<use href="#words"/>
</svg>
